VERSION 5.8 ;
BUSBITCHARS "[]" ;
DIVIDERCHAR "/" ;
UNITS
    DATABASE MICRONS 1000 ;
END UNITS

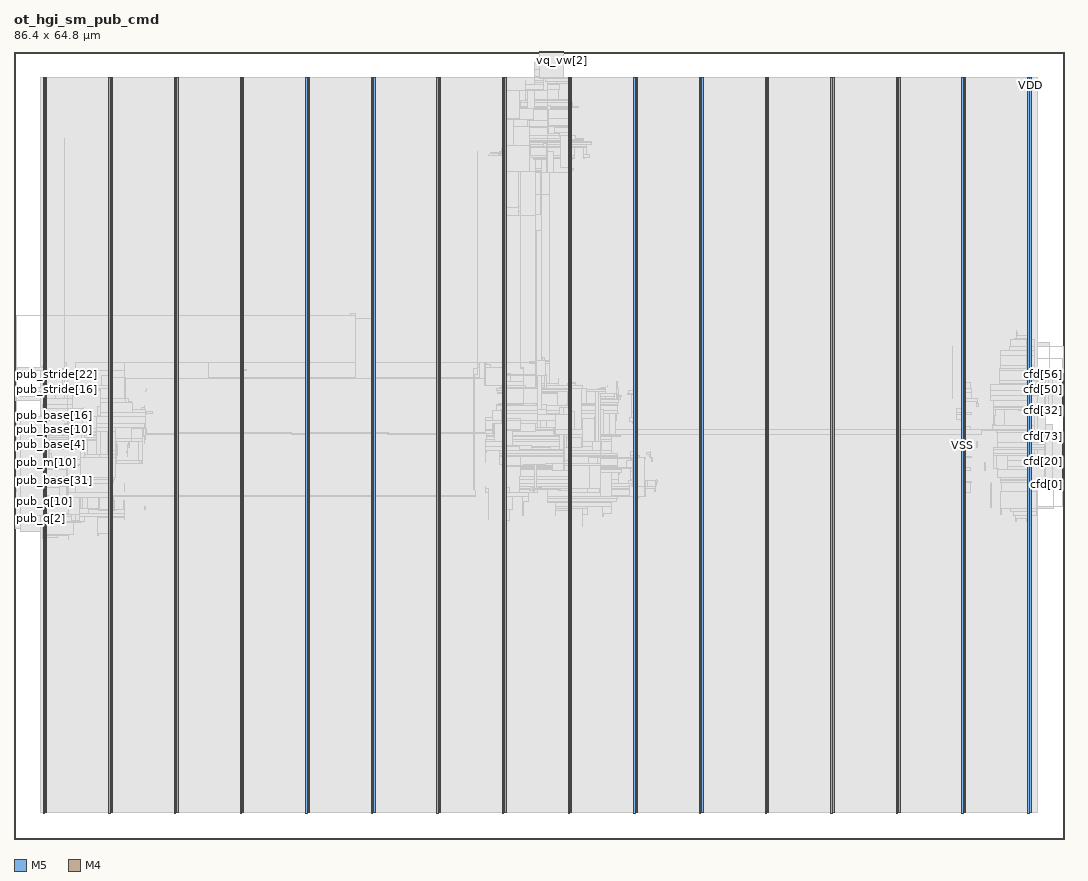
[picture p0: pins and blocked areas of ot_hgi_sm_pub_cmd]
MACRO ot_hgi_sm_pub_cmd
  FOREIGN ot_hgi_sm_pub_cmd 0 0 ;
  CLASS BLOCK ;
  SIZE 86.4 BY 64.8 ;
  PIN agg_r
    DIRECTION INPUT ;
    USE SIGNAL ;
    PORT
      LAYER M5 ;
        RECT  43.248 64.716 43.272 64.8 ;
    END
  END agg_r
  PIN cfd[0]
    DIRECTION OUTPUT ;
    USE SIGNAL ;
    PORT
      LAYER M4 ;
        RECT  86.316 29.136 86.4 29.16 ;
    END
  END cfd[0]
  PIN cfd[10]
    DIRECTION OUTPUT ;
    USE SIGNAL ;
    PORT
      LAYER M4 ;
        RECT  86.316 30.096 86.4 30.12 ;
    END
  END cfd[10]
  PIN cfd[11]
    DIRECTION OUTPUT ;
    USE SIGNAL ;
    PORT
      LAYER M4 ;
        RECT  86.316 30.192 86.4 30.216 ;
    END
  END cfd[11]
  PIN cfd[12]
    DIRECTION OUTPUT ;
    USE SIGNAL ;
    PORT
      LAYER M4 ;
        RECT  86.316 30.288 86.4 30.312 ;
    END
  END cfd[12]
  PIN cfd[13]
    DIRECTION OUTPUT ;
    USE SIGNAL ;
    PORT
      LAYER M4 ;
        RECT  86.316 30.384 86.4 30.408 ;
    END
  END cfd[13]
  PIN cfd[14]
    DIRECTION OUTPUT ;
    USE SIGNAL ;
    PORT
      LAYER M4 ;
        RECT  86.316 30.48 86.4 30.504 ;
    END
  END cfd[14]
  PIN cfd[15]
    DIRECTION OUTPUT ;
    USE SIGNAL ;
    PORT
      LAYER M4 ;
        RECT  86.316 30.576 86.4 30.6 ;
    END
  END cfd[15]
  PIN cfd[16]
    DIRECTION OUTPUT ;
    USE SIGNAL ;
    PORT
      LAYER M4 ;
        RECT  86.316 30.672 86.4 30.696 ;
    END
  END cfd[16]
  PIN cfd[17]
    DIRECTION OUTPUT ;
    USE SIGNAL ;
    PORT
      LAYER M4 ;
        RECT  86.316 30.768 86.4 30.792 ;
    END
  END cfd[17]
  PIN cfd[18]
    DIRECTION OUTPUT ;
    USE SIGNAL ;
    PORT
      LAYER M4 ;
        RECT  86.316 30.864 86.4 30.888 ;
    END
  END cfd[18]
  PIN cfd[19]
    DIRECTION OUTPUT ;
    USE SIGNAL ;
    PORT
      LAYER M4 ;
        RECT  86.316 30.96 86.4 30.984 ;
    END
  END cfd[19]
  PIN cfd[1]
    DIRECTION OUTPUT ;
    USE SIGNAL ;
    PORT
      LAYER M4 ;
        RECT  86.316 29.232 86.4 29.256 ;
    END
  END cfd[1]
  PIN cfd[20]
    DIRECTION OUTPUT ;
    USE SIGNAL ;
    PORT
      LAYER M4 ;
        RECT  86.316 31.056 86.4 31.08 ;
    END
  END cfd[20]
  PIN cfd[21]
    DIRECTION OUTPUT ;
    USE SIGNAL ;
    PORT
      LAYER M4 ;
        RECT  86.316 31.152 86.4 31.176 ;
    END
  END cfd[21]
  PIN cfd[22]
    DIRECTION OUTPUT ;
    USE SIGNAL ;
    PORT
      LAYER M4 ;
        RECT  86.316 31.248 86.4 31.272 ;
    END
  END cfd[22]
  PIN cfd[23]
    DIRECTION OUTPUT ;
    USE SIGNAL ;
    PORT
      LAYER M4 ;
        RECT  86.316 31.344 86.4 31.368 ;
    END
  END cfd[23]
  PIN cfd[24]
    DIRECTION OUTPUT ;
    USE SIGNAL ;
    PORT
      LAYER M4 ;
        RECT  86.316 31.44 86.4 31.464 ;
    END
  END cfd[24]
  PIN cfd[25]
    DIRECTION OUTPUT ;
    USE SIGNAL ;
    PORT
      LAYER M4 ;
        RECT  86.316 31.536 86.4 31.56 ;
    END
  END cfd[25]
  PIN cfd[26]
    DIRECTION OUTPUT ;
    USE SIGNAL ;
    PORT
      LAYER M4 ;
        RECT  86.316 31.632 86.4 31.656 ;
    END
  END cfd[26]
  PIN cfd[27]
    DIRECTION OUTPUT ;
    USE SIGNAL ;
    PORT
      LAYER M4 ;
        RECT  86.316 31.728 86.4 31.752 ;
    END
  END cfd[27]
  PIN cfd[28]
    DIRECTION OUTPUT ;
    USE SIGNAL ;
    PORT
      LAYER M4 ;
        RECT  86.316 31.824 86.4 31.848 ;
    END
  END cfd[28]
  PIN cfd[29]
    DIRECTION OUTPUT ;
    USE SIGNAL ;
    PORT
      LAYER M4 ;
        RECT  86.316 31.92 86.4 31.944 ;
    END
  END cfd[29]
  PIN cfd[2]
    DIRECTION OUTPUT ;
    USE SIGNAL ;
    PORT
      LAYER M4 ;
        RECT  86.316 29.328 86.4 29.352 ;
    END
  END cfd[2]
  PIN cfd[30]
    DIRECTION OUTPUT ;
    USE SIGNAL ;
    PORT
      LAYER M4 ;
        RECT  86.316 32.016 86.4 32.04 ;
    END
  END cfd[30]
  PIN cfd[31]
    DIRECTION OUTPUT ;
    USE SIGNAL ;
    PORT
      LAYER M4 ;
        RECT  86.316 32.112 86.4 32.136 ;
    END
  END cfd[31]
  PIN cfd[32]
    DIRECTION OUTPUT ;
    USE SIGNAL ;
    PORT
      LAYER M4 ;
        RECT  86.316 35.28 86.4 35.304 ;
    END
  END cfd[32]
  PIN cfd[33]
    DIRECTION OUTPUT ;
    USE SIGNAL ;
    PORT
      LAYER M4 ;
        RECT  86.316 35.376 86.4 35.4 ;
    END
  END cfd[33]
  PIN cfd[34]
    DIRECTION OUTPUT ;
    USE SIGNAL ;
    PORT
      LAYER M4 ;
        RECT  86.316 35.472 86.4 35.496 ;
    END
  END cfd[34]
  PIN cfd[35]
    DIRECTION OUTPUT ;
    USE SIGNAL ;
    PORT
      LAYER M4 ;
        RECT  86.316 35.568 86.4 35.592 ;
    END
  END cfd[35]
  PIN cfd[36]
    DIRECTION OUTPUT ;
    USE SIGNAL ;
    PORT
      LAYER M4 ;
        RECT  86.316 35.664 86.4 35.688 ;
    END
  END cfd[36]
  PIN cfd[37]
    DIRECTION OUTPUT ;
    USE SIGNAL ;
    PORT
      LAYER M4 ;
        RECT  86.316 35.76 86.4 35.784 ;
    END
  END cfd[37]
  PIN cfd[38]
    DIRECTION OUTPUT ;
    USE SIGNAL ;
    PORT
      LAYER M4 ;
        RECT  86.316 35.856 86.4 35.88 ;
    END
  END cfd[38]
  PIN cfd[39]
    DIRECTION OUTPUT ;
    USE SIGNAL ;
    PORT
      LAYER M4 ;
        RECT  86.316 35.952 86.4 35.976 ;
    END
  END cfd[39]
  PIN cfd[3]
    DIRECTION OUTPUT ;
    USE SIGNAL ;
    PORT
      LAYER M4 ;
        RECT  86.316 29.424 86.4 29.448 ;
    END
  END cfd[3]
  PIN cfd[40]
    DIRECTION OUTPUT ;
    USE SIGNAL ;
    PORT
      LAYER M4 ;
        RECT  86.316 36.048 86.4 36.072 ;
    END
  END cfd[40]
  PIN cfd[41]
    DIRECTION OUTPUT ;
    USE SIGNAL ;
    PORT
      LAYER M4 ;
        RECT  86.316 36.144 86.4 36.168 ;
    END
  END cfd[41]
  PIN cfd[42]
    DIRECTION OUTPUT ;
    USE SIGNAL ;
    PORT
      LAYER M4 ;
        RECT  86.316 36.24 86.4 36.264 ;
    END
  END cfd[42]
  PIN cfd[43]
    DIRECTION OUTPUT ;
    USE SIGNAL ;
    PORT
      LAYER M4 ;
        RECT  86.316 36.336 86.4 36.36 ;
    END
  END cfd[43]
  PIN cfd[44]
    DIRECTION OUTPUT ;
    USE SIGNAL ;
    PORT
      LAYER M4 ;
        RECT  86.316 36.432 86.4 36.456 ;
    END
  END cfd[44]
  PIN cfd[45]
    DIRECTION OUTPUT ;
    USE SIGNAL ;
    PORT
      LAYER M4 ;
        RECT  86.316 36.528 86.4 36.552 ;
    END
  END cfd[45]
  PIN cfd[46]
    DIRECTION OUTPUT ;
    USE SIGNAL ;
    PORT
      LAYER M4 ;
        RECT  86.316 36.624 86.4 36.648 ;
    END
  END cfd[46]
  PIN cfd[47]
    DIRECTION OUTPUT ;
    USE SIGNAL ;
    PORT
      LAYER M4 ;
        RECT  86.316 36.72 86.4 36.744 ;
    END
  END cfd[47]
  PIN cfd[48]
    DIRECTION OUTPUT ;
    USE SIGNAL ;
    PORT
      LAYER M4 ;
        RECT  86.316 36.816 86.4 36.84 ;
    END
  END cfd[48]
  PIN cfd[49]
    DIRECTION OUTPUT ;
    USE SIGNAL ;
    PORT
      LAYER M4 ;
        RECT  86.316 36.912 86.4 36.936 ;
    END
  END cfd[49]
  PIN cfd[4]
    DIRECTION OUTPUT ;
    USE SIGNAL ;
    PORT
      LAYER M4 ;
        RECT  86.316 29.52 86.4 29.544 ;
    END
  END cfd[4]
  PIN cfd[50]
    DIRECTION OUTPUT ;
    USE SIGNAL ;
    PORT
      LAYER M4 ;
        RECT  86.316 37.008 86.4 37.032 ;
    END
  END cfd[50]
  PIN cfd[51]
    DIRECTION OUTPUT ;
    USE SIGNAL ;
    PORT
      LAYER M4 ;
        RECT  86.316 37.104 86.4 37.128 ;
    END
  END cfd[51]
  PIN cfd[52]
    DIRECTION OUTPUT ;
    USE SIGNAL ;
    PORT
      LAYER M4 ;
        RECT  86.316 37.2 86.4 37.224 ;
    END
  END cfd[52]
  PIN cfd[53]
    DIRECTION OUTPUT ;
    USE SIGNAL ;
    PORT
      LAYER M4 ;
        RECT  86.316 37.296 86.4 37.32 ;
    END
  END cfd[53]
  PIN cfd[54]
    DIRECTION OUTPUT ;
    USE SIGNAL ;
    PORT
      LAYER M4 ;
        RECT  86.316 37.392 86.4 37.416 ;
    END
  END cfd[54]
  PIN cfd[55]
    DIRECTION OUTPUT ;
    USE SIGNAL ;
    PORT
      LAYER M4 ;
        RECT  86.316 37.488 86.4 37.512 ;
    END
  END cfd[55]
  PIN cfd[56]
    DIRECTION OUTPUT ;
    USE SIGNAL ;
    PORT
      LAYER M4 ;
        RECT  86.316 37.584 86.4 37.608 ;
    END
  END cfd[56]
  PIN cfd[57]
    DIRECTION OUTPUT ;
    USE SIGNAL ;
    PORT
      LAYER M4 ;
        RECT  86.316 37.68 86.4 37.704 ;
    END
  END cfd[57]
  PIN cfd[58]
    DIRECTION OUTPUT ;
    USE SIGNAL ;
    PORT
      LAYER M4 ;
        RECT  86.316 37.776 86.4 37.8 ;
    END
  END cfd[58]
  PIN cfd[59]
    DIRECTION OUTPUT ;
    USE SIGNAL ;
    PORT
      LAYER M4 ;
        RECT  86.316 37.872 86.4 37.896 ;
    END
  END cfd[59]
  PIN cfd[5]
    DIRECTION OUTPUT ;
    USE SIGNAL ;
    PORT
      LAYER M4 ;
        RECT  86.316 29.616 86.4 29.64 ;
    END
  END cfd[5]
  PIN cfd[60]
    DIRECTION OUTPUT ;
    USE SIGNAL ;
    PORT
      LAYER M4 ;
        RECT  86.316 37.968 86.4 37.992 ;
    END
  END cfd[60]
  PIN cfd[61]
    DIRECTION OUTPUT ;
    USE SIGNAL ;
    PORT
      LAYER M4 ;
        RECT  86.316 38.064 86.4 38.088 ;
    END
  END cfd[61]
  PIN cfd[62]
    DIRECTION OUTPUT ;
    USE SIGNAL ;
    PORT
      LAYER M4 ;
        RECT  86.316 38.16 86.4 38.184 ;
    END
  END cfd[62]
  PIN cfd[63]
    DIRECTION OUTPUT ;
    USE SIGNAL ;
    PORT
      LAYER M4 ;
        RECT  86.316 38.256 86.4 38.28 ;
    END
  END cfd[63]
  PIN cfd[64]
    DIRECTION OUTPUT ;
    USE SIGNAL ;
    PORT
      LAYER M4 ;
        RECT  86.316 32.208 86.4 32.232 ;
    END
  END cfd[64]
  PIN cfd[65]
    DIRECTION OUTPUT ;
    USE SIGNAL ;
    PORT
      LAYER M4 ;
        RECT  86.316 32.304 86.4 32.328 ;
    END
  END cfd[65]
  PIN cfd[66]
    DIRECTION OUTPUT ;
    USE SIGNAL ;
    PORT
      LAYER M4 ;
        RECT  86.316 32.4 86.4 32.424 ;
    END
  END cfd[66]
  PIN cfd[67]
    DIRECTION OUTPUT ;
    USE SIGNAL ;
    PORT
      LAYER M4 ;
        RECT  86.316 32.496 86.4 32.52 ;
    END
  END cfd[67]
  PIN cfd[68]
    DIRECTION OUTPUT ;
    USE SIGNAL ;
    PORT
      LAYER M4 ;
        RECT  86.316 32.592 86.4 32.616 ;
    END
  END cfd[68]
  PIN cfd[69]
    DIRECTION OUTPUT ;
    USE SIGNAL ;
    PORT
      LAYER M4 ;
        RECT  86.316 32.688 86.4 32.712 ;
    END
  END cfd[69]
  PIN cfd[6]
    DIRECTION OUTPUT ;
    USE SIGNAL ;
    PORT
      LAYER M4 ;
        RECT  86.316 29.712 86.4 29.736 ;
    END
  END cfd[6]
  PIN cfd[70]
    DIRECTION OUTPUT ;
    USE SIGNAL ;
    PORT
      LAYER M4 ;
        RECT  86.316 32.784 86.4 32.808 ;
    END
  END cfd[70]
  PIN cfd[71]
    DIRECTION OUTPUT ;
    USE SIGNAL ;
    PORT
      LAYER M4 ;
        RECT  86.316 32.88 86.4 32.904 ;
    END
  END cfd[71]
  PIN cfd[72]
    DIRECTION OUTPUT ;
    USE SIGNAL ;
    PORT
      LAYER M4 ;
        RECT  86.316 32.976 86.4 33 ;
    END
  END cfd[72]
  PIN cfd[73]
    DIRECTION OUTPUT ;
    USE SIGNAL ;
    PORT
      LAYER M4 ;
        RECT  86.316 33.072 86.4 33.096 ;
    END
  END cfd[73]
  PIN cfd[74]
    DIRECTION OUTPUT ;
    USE SIGNAL ;
    PORT
      LAYER M4 ;
        RECT  86.316 33.168 86.4 33.192 ;
    END
  END cfd[74]
  PIN cfd[7]
    DIRECTION OUTPUT ;
    USE SIGNAL ;
    PORT
      LAYER M4 ;
        RECT  86.316 29.808 86.4 29.832 ;
    END
  END cfd[7]
  PIN cfd[8]
    DIRECTION OUTPUT ;
    USE SIGNAL ;
    PORT
      LAYER M4 ;
        RECT  86.316 29.904 86.4 29.928 ;
    END
  END cfd[8]
  PIN cfd[9]
    DIRECTION OUTPUT ;
    USE SIGNAL ;
    PORT
      LAYER M4 ;
        RECT  86.316 30 86.4 30.024 ;
    END
  END cfd[9]
  PIN cgo
    DIRECTION OUTPUT ;
    USE SIGNAL ;
    PORT
      LAYER M4 ;
        RECT  86.316 33.264 86.4 33.288 ;
    END
  END cgo
  PIN clk
    DIRECTION INPUT ;
    USE SIGNAL ;
    PORT
      LAYER M4 ;
        RECT  0 32.592 0.084 32.616 ;
    END
  END clk
  PIN dn_l[0]
    DIRECTION INPUT ;
    USE SIGNAL ;
    PORT
      LAYER M5 ;
        RECT  43.344 64.716 43.368 64.8 ;
    END
  END dn_l[0]
  PIN dn_l[1]
    DIRECTION INPUT ;
    USE SIGNAL ;
    PORT
      LAYER M5 ;
        RECT  43.44 64.716 43.464 64.8 ;
    END
  END dn_l[1]
  PIN dn_l[2]
    DIRECTION INPUT ;
    USE SIGNAL ;
    PORT
      LAYER M5 ;
        RECT  43.536 64.716 43.56 64.8 ;
    END
  END dn_l[2]
  PIN dn_l[3]
    DIRECTION INPUT ;
    USE SIGNAL ;
    PORT
      LAYER M5 ;
        RECT  43.632 64.716 43.656 64.8 ;
    END
  END dn_l[3]
  PIN dn_l[4]
    DIRECTION INPUT ;
    USE SIGNAL ;
    PORT
      LAYER M5 ;
        RECT  43.728 64.716 43.752 64.8 ;
    END
  END dn_l[4]
  PIN dn_l[5]
    DIRECTION INPUT ;
    USE SIGNAL ;
    PORT
      LAYER M5 ;
        RECT  43.824 64.716 43.848 64.8 ;
    END
  END dn_l[5]
  PIN dn_l[6]
    DIRECTION INPUT ;
    USE SIGNAL ;
    PORT
      LAYER M5 ;
        RECT  43.92 64.716 43.944 64.8 ;
    END
  END dn_l[6]
  PIN dn_l[7]
    DIRECTION INPUT ;
    USE SIGNAL ;
    PORT
      LAYER M5 ;
        RECT  44.016 64.716 44.04 64.8 ;
    END
  END dn_l[7]
  PIN ft_l[0]
    DIRECTION INPUT ;
    USE SIGNAL ;
    PORT
      LAYER M5 ;
        RECT  44.112 64.716 44.136 64.8 ;
    END
  END ft_l[0]
  PIN ft_l[1]
    DIRECTION INPUT ;
    USE SIGNAL ;
    PORT
      LAYER M5 ;
        RECT  44.208 64.716 44.232 64.8 ;
    END
  END ft_l[1]
  PIN ft_l[2]
    DIRECTION INPUT ;
    USE SIGNAL ;
    PORT
      LAYER M5 ;
        RECT  44.304 64.716 44.328 64.8 ;
    END
  END ft_l[2]
  PIN ft_l[3]
    DIRECTION INPUT ;
    USE SIGNAL ;
    PORT
      LAYER M5 ;
        RECT  44.4 64.716 44.424 64.8 ;
    END
  END ft_l[3]
  PIN ft_l[4]
    DIRECTION INPUT ;
    USE SIGNAL ;
    PORT
      LAYER M5 ;
        RECT  44.496 64.716 44.52 64.8 ;
    END
  END ft_l[4]
  PIN ft_l[5]
    DIRECTION INPUT ;
    USE SIGNAL ;
    PORT
      LAYER M5 ;
        RECT  44.592 64.716 44.616 64.8 ;
    END
  END ft_l[5]
  PIN ft_l[6]
    DIRECTION INPUT ;
    USE SIGNAL ;
    PORT
      LAYER M5 ;
        RECT  44.688 64.716 44.712 64.8 ;
    END
  END ft_l[6]
  PIN ft_l[7]
    DIRECTION INPUT ;
    USE SIGNAL ;
    PORT
      LAYER M5 ;
        RECT  44.784 64.716 44.808 64.8 ;
    END
  END ft_l[7]
  PIN pub_base[0]
    DIRECTION INPUT ;
    USE SIGNAL ;
    PORT
      LAYER M4 ;
        RECT  0 32.688 0.084 32.712 ;
    END
  END pub_base[0]
  PIN pub_base[10]
    DIRECTION INPUT ;
    USE SIGNAL ;
    PORT
      LAYER M4 ;
        RECT  0 33.648 0.084 33.672 ;
    END
  END pub_base[10]
  PIN pub_base[11]
    DIRECTION INPUT ;
    USE SIGNAL ;
    PORT
      LAYER M4 ;
        RECT  0 33.744 0.084 33.768 ;
    END
  END pub_base[11]
  PIN pub_base[12]
    DIRECTION INPUT ;
    USE SIGNAL ;
    PORT
      LAYER M4 ;
        RECT  0 33.84 0.084 33.864 ;
    END
  END pub_base[12]
  PIN pub_base[13]
    DIRECTION INPUT ;
    USE SIGNAL ;
    PORT
      LAYER M4 ;
        RECT  0 33.936 0.084 33.96 ;
    END
  END pub_base[13]
  PIN pub_base[14]
    DIRECTION INPUT ;
    USE SIGNAL ;
    PORT
      LAYER M4 ;
        RECT  0 34.032 0.084 34.056 ;
    END
  END pub_base[14]
  PIN pub_base[15]
    DIRECTION INPUT ;
    USE SIGNAL ;
    PORT
      LAYER M4 ;
        RECT  0 34.128 0.084 34.152 ;
    END
  END pub_base[15]
  PIN pub_base[16]
    DIRECTION INPUT ;
    USE SIGNAL ;
    PORT
      LAYER M4 ;
        RECT  0 34.224 0.084 34.248 ;
    END
  END pub_base[16]
  PIN pub_base[17]
    DIRECTION INPUT ;
    USE SIGNAL ;
    PORT
      LAYER M4 ;
        RECT  0 34.32 0.084 34.344 ;
    END
  END pub_base[17]
  PIN pub_base[18]
    DIRECTION INPUT ;
    USE SIGNAL ;
    PORT
      LAYER M4 ;
        RECT  0 34.416 0.084 34.44 ;
    END
  END pub_base[18]
  PIN pub_base[19]
    DIRECTION INPUT ;
    USE SIGNAL ;
    PORT
      LAYER M4 ;
        RECT  0 34.512 0.084 34.536 ;
    END
  END pub_base[19]
  PIN pub_base[1]
    DIRECTION INPUT ;
    USE SIGNAL ;
    PORT
      LAYER M4 ;
        RECT  0 32.784 0.084 32.808 ;
    END
  END pub_base[1]
  PIN pub_base[20]
    DIRECTION INPUT ;
    USE SIGNAL ;
    PORT
      LAYER M4 ;
        RECT  0 34.608 0.084 34.632 ;
    END
  END pub_base[20]
  PIN pub_base[21]
    DIRECTION INPUT ;
    USE SIGNAL ;
    PORT
      LAYER M4 ;
        RECT  0 34.704 0.084 34.728 ;
    END
  END pub_base[21]
  PIN pub_base[22]
    DIRECTION INPUT ;
    USE SIGNAL ;
    PORT
      LAYER M4 ;
        RECT  0 34.8 0.084 34.824 ;
    END
  END pub_base[22]
  PIN pub_base[23]
    DIRECTION INPUT ;
    USE SIGNAL ;
    PORT
      LAYER M4 ;
        RECT  0 34.896 0.084 34.92 ;
    END
  END pub_base[23]
  PIN pub_base[24]
    DIRECTION INPUT ;
    USE SIGNAL ;
    PORT
      LAYER M4 ;
        RECT  0 34.992 0.084 35.016 ;
    END
  END pub_base[24]
  PIN pub_base[25]
    DIRECTION INPUT ;
    USE SIGNAL ;
    PORT
      LAYER M4 ;
        RECT  0 35.088 0.084 35.112 ;
    END
  END pub_base[25]
  PIN pub_base[26]
    DIRECTION INPUT ;
    USE SIGNAL ;
    PORT
      LAYER M4 ;
        RECT  0 35.184 0.084 35.208 ;
    END
  END pub_base[26]
  PIN pub_base[27]
    DIRECTION INPUT ;
    USE SIGNAL ;
    PORT
      LAYER M4 ;
        RECT  0 35.28 0.084 35.304 ;
    END
  END pub_base[27]
  PIN pub_base[28]
    DIRECTION INPUT ;
    USE SIGNAL ;
    PORT
      LAYER M4 ;
        RECT  0 35.376 0.084 35.4 ;
    END
  END pub_base[28]
  PIN pub_base[29]
    DIRECTION INPUT ;
    USE SIGNAL ;
    PORT
      LAYER M4 ;
        RECT  0 35.472 0.084 35.496 ;
    END
  END pub_base[29]
  PIN pub_base[2]
    DIRECTION INPUT ;
    USE SIGNAL ;
    PORT
      LAYER M4 ;
        RECT  0 32.88 0.084 32.904 ;
    END
  END pub_base[2]
  PIN pub_base[30]
    DIRECTION INPUT ;
    USE SIGNAL ;
    PORT
      LAYER M4 ;
        RECT  0 35.568 0.084 35.592 ;
    END
  END pub_base[30]
  PIN pub_base[31]
    DIRECTION INPUT ;
    USE SIGNAL ;
    PORT
      LAYER M4 ;
        RECT  0 29.52 0.084 29.544 ;
    END
  END pub_base[31]
  PIN pub_base[32]
    DIRECTION INPUT ;
    USE SIGNAL ;
    PORT
      LAYER M4 ;
        RECT  0 29.616 0.084 29.64 ;
    END
  END pub_base[32]
  PIN pub_base[33]
    DIRECTION INPUT ;
    USE SIGNAL ;
    PORT
      LAYER M4 ;
        RECT  0 29.712 0.084 29.736 ;
    END
  END pub_base[33]
  PIN pub_base[34]
    DIRECTION INPUT ;
    USE SIGNAL ;
    PORT
      LAYER M4 ;
        RECT  0 29.808 0.084 29.832 ;
    END
  END pub_base[34]
  PIN pub_base[35]
    DIRECTION INPUT ;
    USE SIGNAL ;
    PORT
      LAYER M4 ;
        RECT  0 29.904 0.084 29.928 ;
    END
  END pub_base[35]
  PIN pub_base[36]
    DIRECTION INPUT ;
    USE SIGNAL ;
    PORT
      LAYER M4 ;
        RECT  0 30 0.084 30.024 ;
    END
  END pub_base[36]
  PIN pub_base[37]
    DIRECTION INPUT ;
    USE SIGNAL ;
    PORT
      LAYER M4 ;
        RECT  0 30.096 0.084 30.12 ;
    END
  END pub_base[37]
  PIN pub_base[38]
    DIRECTION INPUT ;
    USE SIGNAL ;
    PORT
      LAYER M4 ;
        RECT  0 30.192 0.084 30.216 ;
    END
  END pub_base[38]
  PIN pub_base[39]
    DIRECTION INPUT ;
    USE SIGNAL ;
    PORT
      LAYER M4 ;
        RECT  0 30.288 0.084 30.312 ;
    END
  END pub_base[39]
  PIN pub_base[3]
    DIRECTION INPUT ;
    USE SIGNAL ;
    PORT
      LAYER M4 ;
        RECT  0 32.976 0.084 33 ;
    END
  END pub_base[3]
  PIN pub_base[4]
    DIRECTION INPUT ;
    USE SIGNAL ;
    PORT
      LAYER M4 ;
        RECT  0 33.072 0.084 33.096 ;
    END
  END pub_base[4]
  PIN pub_base[5]
    DIRECTION INPUT ;
    USE SIGNAL ;
    PORT
      LAYER M4 ;
        RECT  0 33.168 0.084 33.192 ;
    END
  END pub_base[5]
  PIN pub_base[6]
    DIRECTION INPUT ;
    USE SIGNAL ;
    PORT
      LAYER M4 ;
        RECT  0 33.264 0.084 33.288 ;
    END
  END pub_base[6]
  PIN pub_base[7]
    DIRECTION INPUT ;
    USE SIGNAL ;
    PORT
      LAYER M4 ;
        RECT  0 33.36 0.084 33.384 ;
    END
  END pub_base[7]
  PIN pub_base[8]
    DIRECTION INPUT ;
    USE SIGNAL ;
    PORT
      LAYER M4 ;
        RECT  0 33.456 0.084 33.48 ;
    END
  END pub_base[8]
  PIN pub_base[9]
    DIRECTION INPUT ;
    USE SIGNAL ;
    PORT
      LAYER M4 ;
        RECT  0 33.552 0.084 33.576 ;
    END
  END pub_base[9]
  PIN pub_bf16
    DIRECTION INPUT ;
    USE SIGNAL ;
    PORT
      LAYER M4 ;
        RECT  0 30.384 0.084 30.408 ;
    END
  END pub_bf16
  PIN pub_done
    DIRECTION OUTPUT ;
    USE SIGNAL ;
    PORT
      LAYER M4 ;
        RECT  0 30.48 0.084 30.504 ;
    END
  END pub_done
  PIN pub_fault
    DIRECTION OUTPUT ;
    USE SIGNAL ;
    PORT
      LAYER M4 ;
        RECT  0 30.576 0.084 30.6 ;
    END
  END pub_fault
  PIN pub_m[0]
    DIRECTION INPUT ;
    USE SIGNAL ;
    PORT
      LAYER M4 ;
        RECT  0 30.672 0.084 30.696 ;
    END
  END pub_m[0]
  PIN pub_m[10]
    DIRECTION INPUT ;
    USE SIGNAL ;
    PORT
      LAYER M4 ;
        RECT  0 31.632 0.084 31.656 ;
    END
  END pub_m[10]
  PIN pub_m[11]
    DIRECTION INPUT ;
    USE SIGNAL ;
    PORT
      LAYER M4 ;
        RECT  0 31.728 0.084 31.752 ;
    END
  END pub_m[11]
  PIN pub_m[12]
    DIRECTION INPUT ;
    USE SIGNAL ;
    PORT
      LAYER M4 ;
        RECT  0 31.824 0.084 31.848 ;
    END
  END pub_m[12]
  PIN pub_m[13]
    DIRECTION INPUT ;
    USE SIGNAL ;
    PORT
      LAYER M4 ;
        RECT  0 31.92 0.084 31.944 ;
    END
  END pub_m[13]
  PIN pub_m[14]
    DIRECTION INPUT ;
    USE SIGNAL ;
    PORT
      LAYER M4 ;
        RECT  0 32.016 0.084 32.04 ;
    END
  END pub_m[14]
  PIN pub_m[15]
    DIRECTION INPUT ;
    USE SIGNAL ;
    PORT
      LAYER M4 ;
        RECT  0 32.112 0.084 32.136 ;
    END
  END pub_m[15]
  PIN pub_m[16]
    DIRECTION INPUT ;
    USE SIGNAL ;
    PORT
      LAYER M4 ;
        RECT  0 32.208 0.084 32.232 ;
    END
  END pub_m[16]
  PIN pub_m[17]
    DIRECTION INPUT ;
    USE SIGNAL ;
    PORT
      LAYER M4 ;
        RECT  0 32.304 0.084 32.328 ;
    END
  END pub_m[17]
  PIN pub_m[18]
    DIRECTION INPUT ;
    USE SIGNAL ;
    PORT
      LAYER M4 ;
        RECT  0 32.4 0.084 32.424 ;
    END
  END pub_m[18]
  PIN pub_m[19]
    DIRECTION INPUT ;
    USE SIGNAL ;
    PORT
      LAYER M4 ;
        RECT  0 32.496 0.084 32.52 ;
    END
  END pub_m[19]
  PIN pub_m[1]
    DIRECTION INPUT ;
    USE SIGNAL ;
    PORT
      LAYER M4 ;
        RECT  0 30.768 0.084 30.792 ;
    END
  END pub_m[1]
  PIN pub_m[2]
    DIRECTION INPUT ;
    USE SIGNAL ;
    PORT
      LAYER M4 ;
        RECT  0 30.864 0.084 30.888 ;
    END
  END pub_m[2]
  PIN pub_m[3]
    DIRECTION INPUT ;
    USE SIGNAL ;
    PORT
      LAYER M4 ;
        RECT  0 30.96 0.084 30.984 ;
    END
  END pub_m[3]
  PIN pub_m[4]
    DIRECTION INPUT ;
    USE SIGNAL ;
    PORT
      LAYER M4 ;
        RECT  0 31.056 0.084 31.08 ;
    END
  END pub_m[4]
  PIN pub_m[5]
    DIRECTION INPUT ;
    USE SIGNAL ;
    PORT
      LAYER M4 ;
        RECT  0 31.152 0.084 31.176 ;
    END
  END pub_m[5]
  PIN pub_m[6]
    DIRECTION INPUT ;
    USE SIGNAL ;
    PORT
      LAYER M4 ;
        RECT  0 31.248 0.084 31.272 ;
    END
  END pub_m[6]
  PIN pub_m[7]
    DIRECTION INPUT ;
    USE SIGNAL ;
    PORT
      LAYER M4 ;
        RECT  0 31.344 0.084 31.368 ;
    END
  END pub_m[7]
  PIN pub_m[8]
    DIRECTION INPUT ;
    USE SIGNAL ;
    PORT
      LAYER M4 ;
        RECT  0 31.44 0.084 31.464 ;
    END
  END pub_m[8]
  PIN pub_m[9]
    DIRECTION INPUT ;
    USE SIGNAL ;
    PORT
      LAYER M4 ;
        RECT  0 31.536 0.084 31.56 ;
    END
  END pub_m[9]
  PIN pub_p[0]
    DIRECTION INPUT ;
    USE SIGNAL ;
    PORT
      LAYER M4 ;
        RECT  0 26.448 0.084 26.472 ;
    END
  END pub_p[0]
  PIN pub_p[1]
    DIRECTION INPUT ;
    USE SIGNAL ;
    PORT
      LAYER M4 ;
        RECT  0 26.544 0.084 26.568 ;
    END
  END pub_p[1]
  PIN pub_p[2]
    DIRECTION INPUT ;
    USE SIGNAL ;
    PORT
      LAYER M4 ;
        RECT  0 26.64 0.084 26.664 ;
    END
  END pub_p[2]
  PIN pub_p[3]
    DIRECTION INPUT ;
    USE SIGNAL ;
    PORT
      LAYER M4 ;
        RECT  0 26.736 0.084 26.76 ;
    END
  END pub_p[3]
  PIN pub_q[0]
    DIRECTION INPUT ;
    USE SIGNAL ;
    PORT
      LAYER M4 ;
        RECT  0 26.832 0.084 26.856 ;
    END
  END pub_q[0]
  PIN pub_q[10]
    DIRECTION INPUT ;
    USE SIGNAL ;
    PORT
      LAYER M4 ;
        RECT  0 27.792 0.084 27.816 ;
    END
  END pub_q[10]
  PIN pub_q[11]
    DIRECTION INPUT ;
    USE SIGNAL ;
    PORT
      LAYER M4 ;
        RECT  0 27.888 0.084 27.912 ;
    END
  END pub_q[11]
  PIN pub_q[12]
    DIRECTION INPUT ;
    USE SIGNAL ;
    PORT
      LAYER M4 ;
        RECT  0 27.984 0.084 28.008 ;
    END
  END pub_q[12]
  PIN pub_q[1]
    DIRECTION INPUT ;
    USE SIGNAL ;
    PORT
      LAYER M4 ;
        RECT  0 26.928 0.084 26.952 ;
    END
  END pub_q[1]
  PIN pub_q[2]
    DIRECTION INPUT ;
    USE SIGNAL ;
    PORT
      LAYER M4 ;
        RECT  0 27.024 0.084 27.048 ;
    END
  END pub_q[2]
  PIN pub_q[3]
    DIRECTION INPUT ;
    USE SIGNAL ;
    PORT
      LAYER M4 ;
        RECT  0 27.12 0.084 27.144 ;
    END
  END pub_q[3]
  PIN pub_q[4]
    DIRECTION INPUT ;
    USE SIGNAL ;
    PORT
      LAYER M4 ;
        RECT  0 27.216 0.084 27.24 ;
    END
  END pub_q[4]
  PIN pub_q[5]
    DIRECTION INPUT ;
    USE SIGNAL ;
    PORT
      LAYER M4 ;
        RECT  0 27.312 0.084 27.336 ;
    END
  END pub_q[5]
  PIN pub_q[6]
    DIRECTION INPUT ;
    USE SIGNAL ;
    PORT
      LAYER M4 ;
        RECT  0 27.408 0.084 27.432 ;
    END
  END pub_q[6]
  PIN pub_q[7]
    DIRECTION INPUT ;
    USE SIGNAL ;
    PORT
      LAYER M4 ;
        RECT  0 27.504 0.084 27.528 ;
    END
  END pub_q[7]
  PIN pub_q[8]
    DIRECTION INPUT ;
    USE SIGNAL ;
    PORT
      LAYER M4 ;
        RECT  0 27.6 0.084 27.624 ;
    END
  END pub_q[8]
  PIN pub_q[9]
    DIRECTION INPUT ;
    USE SIGNAL ;
    PORT
      LAYER M4 ;
        RECT  0 27.696 0.084 27.72 ;
    END
  END pub_q[9]
  PIN pub_rdy
    DIRECTION OUTPUT ;
    USE SIGNAL ;
    PORT
      LAYER M4 ;
        RECT  0 28.08 0.084 28.104 ;
    END
  END pub_rdy
  PIN pub_space[0]
    DIRECTION INPUT ;
    USE SIGNAL ;
    PORT
      LAYER M4 ;
        RECT  0 28.176 0.084 28.2 ;
    END
  END pub_space[0]
  PIN pub_space[1]
    DIRECTION INPUT ;
    USE SIGNAL ;
    PORT
      LAYER M4 ;
        RECT  0 28.272 0.084 28.296 ;
    END
  END pub_space[1]
  PIN pub_stride[0]
    DIRECTION INPUT ;
    USE SIGNAL ;
    PORT
      LAYER M4 ;
        RECT  0 28.368 0.084 28.392 ;
    END
  END pub_stride[0]
  PIN pub_stride[10]
    DIRECTION INPUT ;
    USE SIGNAL ;
    PORT
      LAYER M4 ;
        RECT  0 29.328 0.084 29.352 ;
    END
  END pub_stride[10]
  PIN pub_stride[11]
    DIRECTION INPUT ;
    USE SIGNAL ;
    PORT
      LAYER M4 ;
        RECT  0 29.424 0.084 29.448 ;
    END
  END pub_stride[11]
  PIN pub_stride[12]
    DIRECTION INPUT ;
    USE SIGNAL ;
    PORT
      LAYER M4 ;
        RECT  0 36.624 0.084 36.648 ;
    END
  END pub_stride[12]
  PIN pub_stride[13]
    DIRECTION INPUT ;
    USE SIGNAL ;
    PORT
      LAYER M4 ;
        RECT  0 36.72 0.084 36.744 ;
    END
  END pub_stride[13]
  PIN pub_stride[14]
    DIRECTION INPUT ;
    USE SIGNAL ;
    PORT
      LAYER M4 ;
        RECT  0 36.816 0.084 36.84 ;
    END
  END pub_stride[14]
  PIN pub_stride[15]
    DIRECTION INPUT ;
    USE SIGNAL ;
    PORT
      LAYER M4 ;
        RECT  0 36.912 0.084 36.936 ;
    END
  END pub_stride[15]
  PIN pub_stride[16]
    DIRECTION INPUT ;
    USE SIGNAL ;
    PORT
      LAYER M4 ;
        RECT  0 37.008 0.084 37.032 ;
    END
  END pub_stride[16]
  PIN pub_stride[17]
    DIRECTION INPUT ;
    USE SIGNAL ;
    PORT
      LAYER M4 ;
        RECT  0 37.104 0.084 37.128 ;
    END
  END pub_stride[17]
  PIN pub_stride[18]
    DIRECTION INPUT ;
    USE SIGNAL ;
    PORT
      LAYER M4 ;
        RECT  0 37.2 0.084 37.224 ;
    END
  END pub_stride[18]
  PIN pub_stride[19]
    DIRECTION INPUT ;
    USE SIGNAL ;
    PORT
      LAYER M4 ;
        RECT  0 37.296 0.084 37.32 ;
    END
  END pub_stride[19]
  PIN pub_stride[1]
    DIRECTION INPUT ;
    USE SIGNAL ;
    PORT
      LAYER M4 ;
        RECT  0 28.464 0.084 28.488 ;
    END
  END pub_stride[1]
  PIN pub_stride[20]
    DIRECTION INPUT ;
    USE SIGNAL ;
    PORT
      LAYER M4 ;
        RECT  0 37.392 0.084 37.416 ;
    END
  END pub_stride[20]
  PIN pub_stride[21]
    DIRECTION INPUT ;
    USE SIGNAL ;
    PORT
      LAYER M4 ;
        RECT  0 37.488 0.084 37.512 ;
    END
  END pub_stride[21]
  PIN pub_stride[22]
    DIRECTION INPUT ;
    USE SIGNAL ;
    PORT
      LAYER M4 ;
        RECT  0 37.584 0.084 37.608 ;
    END
  END pub_stride[22]
  PIN pub_stride[23]
    DIRECTION INPUT ;
    USE SIGNAL ;
    PORT
      LAYER M4 ;
        RECT  0 37.68 0.084 37.704 ;
    END
  END pub_stride[23]
  PIN pub_stride[24]
    DIRECTION INPUT ;
    USE SIGNAL ;
    PORT
      LAYER M4 ;
        RECT  0 37.776 0.084 37.8 ;
    END
  END pub_stride[24]
  PIN pub_stride[25]
    DIRECTION INPUT ;
    USE SIGNAL ;
    PORT
      LAYER M4 ;
        RECT  0 37.872 0.084 37.896 ;
    END
  END pub_stride[25]
  PIN pub_stride[26]
    DIRECTION INPUT ;
    USE SIGNAL ;
    PORT
      LAYER M4 ;
        RECT  0 37.968 0.084 37.992 ;
    END
  END pub_stride[26]
  PIN pub_stride[27]
    DIRECTION INPUT ;
    USE SIGNAL ;
    PORT
      LAYER M4 ;
        RECT  0 38.064 0.084 38.088 ;
    END
  END pub_stride[27]
  PIN pub_stride[28]
    DIRECTION INPUT ;
    USE SIGNAL ;
    PORT
      LAYER M4 ;
        RECT  0 38.16 0.084 38.184 ;
    END
  END pub_stride[28]
  PIN pub_stride[29]
    DIRECTION INPUT ;
    USE SIGNAL ;
    PORT
      LAYER M4 ;
        RECT  0 38.256 0.084 38.28 ;
    END
  END pub_stride[29]
  PIN pub_stride[2]
    DIRECTION INPUT ;
    USE SIGNAL ;
    PORT
      LAYER M4 ;
        RECT  0 28.56 0.084 28.584 ;
    END
  END pub_stride[2]
  PIN pub_stride[30]
    DIRECTION INPUT ;
    USE SIGNAL ;
    PORT
      LAYER M4 ;
        RECT  0 38.352 0.084 38.376 ;
    END
  END pub_stride[30]
  PIN pub_stride[31]
    DIRECTION INPUT ;
    USE SIGNAL ;
    PORT
      LAYER M4 ;
        RECT  0 38.448 0.084 38.472 ;
    END
  END pub_stride[31]
  PIN pub_stride[3]
    DIRECTION INPUT ;
    USE SIGNAL ;
    PORT
      LAYER M4 ;
        RECT  0 28.656 0.084 28.68 ;
    END
  END pub_stride[3]
  PIN pub_stride[4]
    DIRECTION INPUT ;
    USE SIGNAL ;
    PORT
      LAYER M4 ;
        RECT  0 28.752 0.084 28.776 ;
    END
  END pub_stride[4]
  PIN pub_stride[5]
    DIRECTION INPUT ;
    USE SIGNAL ;
    PORT
      LAYER M4 ;
        RECT  0 28.848 0.084 28.872 ;
    END
  END pub_stride[5]
  PIN pub_stride[6]
    DIRECTION INPUT ;
    USE SIGNAL ;
    PORT
      LAYER M4 ;
        RECT  0 28.944 0.084 28.968 ;
    END
  END pub_stride[6]
  PIN pub_stride[7]
    DIRECTION INPUT ;
    USE SIGNAL ;
    PORT
      LAYER M4 ;
        RECT  0 29.04 0.084 29.064 ;
    END
  END pub_stride[7]
  PIN pub_stride[8]
    DIRECTION INPUT ;
    USE SIGNAL ;
    PORT
      LAYER M4 ;
        RECT  0 29.136 0.084 29.16 ;
    END
  END pub_stride[8]
  PIN pub_stride[9]
    DIRECTION INPUT ;
    USE SIGNAL ;
    PORT
      LAYER M4 ;
        RECT  0 29.232 0.084 29.256 ;
    END
  END pub_stride[9]
  PIN pub_v
    DIRECTION INPUT ;
    USE SIGNAL ;
    PORT
      LAYER M4 ;
        RECT  0 38.544 0.084 38.568 ;
    END
  END pub_v
  PIN rn
    DIRECTION INPUT ;
    USE SIGNAL ;
    PORT
      LAYER M4 ;
        RECT  0 38.64 0.084 38.664 ;
    END
  END rn
  PIN vq_vw[0]
    DIRECTION INPUT ;
    USE SIGNAL ;
    PORT
      LAYER M5 ;
        RECT  44.88 64.716 44.904 64.8 ;
    END
  END vq_vw[0]
  PIN vq_vw[1]
    DIRECTION INPUT ;
    USE SIGNAL ;
    PORT
      LAYER M5 ;
        RECT  44.976 64.716 45 64.8 ;
    END
  END vq_vw[1]
  PIN vq_vw[2]
    DIRECTION INPUT ;
    USE SIGNAL ;
    PORT
      LAYER M5 ;
        RECT  45.072 64.716 45.096 64.8 ;
    END
  END vq_vw[2]
  PIN vq_vw[3]
    DIRECTION INPUT ;
    USE SIGNAL ;
    PORT
      LAYER M5 ;
        RECT  45.168 64.716 45.192 64.8 ;
    END
  END vq_vw[3]
  PIN VDD
    DIRECTION INOUT ;
    USE POWER ;
    PORT
      LAYER M5 ;
        RECT  83.592 2.151 83.712 62.649 ;
        RECT  78.192 2.151 78.312 62.649 ;
        RECT  72.792 2.151 72.912 62.649 ;
        RECT  67.392 2.151 67.512 62.649 ;
        RECT  61.992 2.151 62.112 62.649 ;
        RECT  56.592 2.151 56.712 62.649 ;
        RECT  51.192 2.151 51.312 62.649 ;
        RECT  45.792 2.151 45.912 62.649 ;
        RECT  40.392 2.151 40.512 62.649 ;
        RECT  34.992 2.151 35.112 62.649 ;
        RECT  29.592 2.151 29.712 62.649 ;
        RECT  24.192 2.151 24.312 62.649 ;
        RECT  18.792 2.151 18.912 62.649 ;
        RECT  13.392 2.151 13.512 62.649 ;
        RECT  7.992 2.151 8.112 62.649 ;
        RECT  2.592 2.151 2.712 62.649 ;
    END
  END VDD
  PIN VSS
    DIRECTION INOUT ;
    USE GROUND ;
    PORT
      LAYER M5 ;
        RECT  83.4 2.137 83.52 62.663 ;
        RECT  78 2.137 78.12 62.663 ;
        RECT  72.6 2.137 72.72 62.663 ;
        RECT  67.2 2.137 67.32 62.663 ;
        RECT  61.8 2.137 61.92 62.663 ;
        RECT  56.4 2.137 56.52 62.663 ;
        RECT  51 2.137 51.12 62.663 ;
        RECT  45.6 2.137 45.72 62.663 ;
        RECT  40.2 2.137 40.32 62.663 ;
        RECT  34.8 2.137 34.92 62.663 ;
        RECT  29.4 2.137 29.52 62.663 ;
        RECT  24 2.137 24.12 62.663 ;
        RECT  18.6 2.137 18.72 62.663 ;
        RECT  13.2 2.137 13.32 62.663 ;
        RECT  7.8 2.137 7.92 62.663 ;
        RECT  2.4 2.137 2.52 62.663 ;
    END
  END VSS
  # OT_OBS_CLOSED layer=M5 d_um=1.536 added=32
  OBS
    LAYER RVTN ;
     RECT  2.16 2.16 84.24 2.295 ;
     RECT  2.16 2.565 84.24 2.835 ;
     RECT  2.16 3.105 84.24 3.375 ;
     RECT  2.16 3.645 84.24 3.915 ;
     RECT  2.16 4.185 84.24 4.455 ;
     RECT  2.16 4.725 84.24 4.995 ;
     RECT  2.16 5.265 84.24 5.535 ;
     RECT  2.16 5.805 84.24 6.075 ;
     RECT  2.16 6.345 84.24 6.615 ;
     RECT  2.16 6.885 84.24 7.155 ;
     RECT  2.16 7.425 84.24 7.695 ;
     RECT  2.16 7.965 84.24 8.235 ;
     RECT  2.16 8.505 84.24 8.775 ;
     RECT  2.16 9.045 84.24 9.315 ;
     RECT  2.16 9.585 84.24 9.855 ;
     RECT  2.16 10.125 84.24 10.395 ;
     RECT  2.16 10.665 84.24 10.935 ;
     RECT  2.16 11.205 84.24 11.475 ;
     RECT  2.16 11.745 84.24 12.015 ;
     RECT  2.16 12.285 84.24 12.555 ;
     RECT  2.16 12.825 84.24 13.095 ;
     RECT  2.16 13.365 84.24 13.635 ;
     RECT  2.16 13.905 84.24 14.175 ;
     RECT  2.16 14.445 84.24 14.715 ;
     RECT  2.16 14.985 84.24 15.255 ;
     RECT  2.16 15.525 84.24 15.795 ;
     RECT  2.16 16.065 84.24 16.335 ;
     RECT  2.16 16.605 84.24 16.875 ;
     RECT  2.16 17.145 84.24 17.415 ;
     RECT  2.16 17.685 84.24 17.955 ;
     RECT  2.16 18.225 84.24 18.495 ;
     RECT  2.16 18.765 84.24 19.035 ;
     RECT  2.16 19.305 84.24 19.575 ;
     RECT  2.16 19.845 84.24 20.115 ;
     RECT  2.16 20.385 84.24 20.655 ;
     RECT  2.16 20.925 84.24 21.195 ;
     RECT  2.16 21.465 84.24 21.735 ;
     RECT  2.16 22.005 84.24 22.275 ;
     RECT  2.16 22.545 84.24 22.815 ;
     RECT  2.16 23.085 84.24 23.355 ;
     RECT  2.16 23.625 84.24 23.895 ;
     RECT  2.16 24.165 84.24 24.435 ;
     RECT  2.16 24.705 84.24 24.975 ;
     RECT  2.16 25.245 84.24 25.515 ;
     RECT  2.16 25.785 84.24 26.055 ;
     RECT  2.16 26.325 84.24 26.595 ;
     RECT  2.16 26.865 84.24 27.135 ;
     RECT  2.16 27.405 84.24 27.675 ;
     RECT  2.16 27.945 84.24 28.215 ;
     RECT  2.16 28.485 84.24 28.755 ;
     RECT  2.16 29.025 84.24 29.295 ;
     RECT  2.16 29.565 84.24 29.835 ;
     RECT  2.16 30.105 84.24 30.375 ;
     RECT  2.16 30.645 84.24 30.915 ;
     RECT  2.16 31.185 84.24 31.455 ;
     RECT  2.16 31.725 84.24 31.995 ;
     RECT  2.16 32.265 84.24 32.535 ;
     RECT  2.16 32.805 84.24 33.075 ;
     RECT  2.16 33.345 84.24 33.615 ;
     RECT  2.16 33.885 84.24 34.155 ;
     RECT  2.16 34.425 84.24 34.695 ;
     RECT  2.16 34.965 84.24 35.235 ;
     RECT  2.16 35.505 84.24 35.775 ;
     RECT  2.16 36.045 84.24 36.315 ;
     RECT  2.16 36.585 84.24 36.855 ;
     RECT  2.16 37.125 84.24 37.395 ;
     RECT  2.16 37.665 84.24 37.935 ;
     RECT  2.16 38.205 84.24 38.475 ;
     RECT  2.16 38.745 84.24 39.015 ;
     RECT  2.16 39.285 84.24 39.555 ;
     RECT  2.16 39.825 84.24 40.095 ;
     RECT  2.16 40.365 84.24 40.635 ;
     RECT  2.16 40.905 84.24 41.175 ;
     RECT  2.16 41.445 84.24 41.715 ;
     RECT  2.16 41.985 84.24 42.255 ;
     RECT  2.16 42.525 84.24 42.795 ;
     RECT  2.16 43.065 84.24 43.335 ;
     RECT  2.16 43.605 84.24 43.875 ;
     RECT  2.16 44.145 84.24 44.415 ;
     RECT  2.16 44.685 84.24 44.955 ;
     RECT  2.16 45.225 84.24 45.495 ;
     RECT  2.16 45.765 84.24 46.035 ;
     RECT  2.16 46.305 84.24 46.575 ;
     RECT  2.16 46.845 84.24 47.115 ;
     RECT  2.16 47.385 84.24 47.655 ;
     RECT  2.16 47.925 84.24 48.195 ;
     RECT  2.16 48.465 84.24 48.735 ;
     RECT  2.16 49.005 84.24 49.275 ;
     RECT  2.16 49.545 84.24 49.815 ;
     RECT  2.16 50.085 84.24 50.355 ;
     RECT  2.16 50.625 84.24 50.895 ;
     RECT  2.16 51.165 84.24 51.435 ;
     RECT  2.16 51.705 84.24 51.975 ;
     RECT  2.16 52.245 84.24 52.515 ;
     RECT  2.16 52.785 84.24 53.055 ;
     RECT  2.16 53.325 84.24 53.595 ;
     RECT  2.16 53.865 84.24 54.135 ;
     RECT  2.16 54.405 84.24 54.675 ;
     RECT  2.16 54.945 84.24 55.215 ;
     RECT  2.16 55.485 84.24 55.755 ;
     RECT  2.16 56.025 84.24 56.295 ;
     RECT  2.16 56.565 84.24 56.835 ;
     RECT  2.16 57.105 84.24 57.375 ;
     RECT  2.16 57.645 84.24 57.915 ;
     RECT  2.16 58.185 84.24 58.455 ;
     RECT  2.16 58.725 84.24 58.995 ;
     RECT  2.16 59.265 84.24 59.535 ;
     RECT  2.16 59.805 84.24 60.075 ;
     RECT  2.16 60.345 84.24 60.615 ;
     RECT  2.16 60.885 84.24 61.155 ;
     RECT  2.16 61.425 84.24 61.695 ;
     RECT  2.16 61.965 84.24 62.235 ;
     RECT  2.16 62.505 84.24 62.64 ;
    LAYER RVTP ;
     RECT  2.16 2.295 84.24 2.565 ;
     RECT  2.16 2.835 84.24 3.105 ;
     RECT  2.16 3.375 84.24 3.645 ;
     RECT  2.16 3.915 84.24 4.185 ;
     RECT  2.16 4.455 84.24 4.725 ;
     RECT  2.16 4.995 84.24 5.265 ;
     RECT  2.16 5.535 84.24 5.805 ;
     RECT  2.16 6.075 84.24 6.345 ;
     RECT  2.16 6.615 84.24 6.885 ;
     RECT  2.16 7.155 84.24 7.425 ;
     RECT  2.16 7.695 84.24 7.965 ;
     RECT  2.16 8.235 84.24 8.505 ;
     RECT  2.16 8.775 84.24 9.045 ;
     RECT  2.16 9.315 84.24 9.585 ;
     RECT  2.16 9.855 84.24 10.125 ;
     RECT  2.16 10.395 84.24 10.665 ;
     RECT  2.16 10.935 84.24 11.205 ;
     RECT  2.16 11.475 84.24 11.745 ;
     RECT  2.16 12.015 84.24 12.285 ;
     RECT  2.16 12.555 84.24 12.825 ;
     RECT  2.16 13.095 84.24 13.365 ;
     RECT  2.16 13.635 84.24 13.905 ;
     RECT  2.16 14.175 84.24 14.445 ;
     RECT  2.16 14.715 84.24 14.985 ;
     RECT  2.16 15.255 84.24 15.525 ;
     RECT  2.16 15.795 84.24 16.065 ;
     RECT  2.16 16.335 84.24 16.605 ;
     RECT  2.16 16.875 84.24 17.145 ;
     RECT  2.16 17.415 84.24 17.685 ;
     RECT  2.16 17.955 84.24 18.225 ;
     RECT  2.16 18.495 84.24 18.765 ;
     RECT  2.16 19.035 84.24 19.305 ;
     RECT  2.16 19.575 84.24 19.845 ;
     RECT  2.16 20.115 84.24 20.385 ;
     RECT  2.16 20.655 84.24 20.925 ;
     RECT  2.16 21.195 84.24 21.465 ;
     RECT  2.16 21.735 84.24 22.005 ;
     RECT  2.16 22.275 84.24 22.545 ;
     RECT  2.16 22.815 84.24 23.085 ;
     RECT  2.16 23.355 84.24 23.625 ;
     RECT  2.16 23.895 84.24 24.165 ;
     RECT  2.16 24.435 84.24 24.705 ;
     RECT  2.16 24.975 84.24 25.245 ;
     RECT  2.16 25.515 84.24 25.785 ;
     RECT  2.16 26.055 84.24 26.325 ;
     RECT  2.16 26.595 84.24 26.865 ;
     RECT  2.16 27.135 84.24 27.405 ;
     RECT  2.16 27.675 84.24 27.945 ;
     RECT  2.16 28.215 84.24 28.485 ;
     RECT  2.16 28.755 84.24 29.025 ;
     RECT  2.16 29.295 84.24 29.565 ;
     RECT  2.16 29.835 84.24 30.105 ;
     RECT  2.16 30.375 84.24 30.645 ;
     RECT  2.16 30.915 84.24 31.185 ;
     RECT  2.16 31.455 84.24 31.725 ;
     RECT  2.16 31.995 84.24 32.265 ;
     RECT  2.16 32.535 84.24 32.805 ;
     RECT  2.16 33.075 84.24 33.345 ;
     RECT  2.16 33.615 84.24 33.885 ;
     RECT  2.16 34.155 84.24 34.425 ;
     RECT  2.16 34.695 84.24 34.965 ;
     RECT  2.16 35.235 84.24 35.505 ;
     RECT  2.16 35.775 84.24 36.045 ;
     RECT  2.16 36.315 84.24 36.585 ;
     RECT  2.16 36.855 84.24 37.125 ;
     RECT  2.16 37.395 84.24 37.665 ;
     RECT  2.16 37.935 84.24 38.205 ;
     RECT  2.16 38.475 84.24 38.745 ;
     RECT  2.16 39.015 84.24 39.285 ;
     RECT  2.16 39.555 84.24 39.825 ;
     RECT  2.16 40.095 84.24 40.365 ;
     RECT  2.16 40.635 84.24 40.905 ;
     RECT  2.16 41.175 84.24 41.445 ;
     RECT  2.16 41.715 84.24 41.985 ;
     RECT  2.16 42.255 84.24 42.525 ;
     RECT  2.16 42.795 84.24 43.065 ;
     RECT  2.16 43.335 84.24 43.605 ;
     RECT  2.16 43.875 84.24 44.145 ;
     RECT  2.16 44.415 84.24 44.685 ;
     RECT  2.16 44.955 84.24 45.225 ;
     RECT  2.16 45.495 84.24 45.765 ;
     RECT  2.16 46.035 84.24 46.305 ;
     RECT  2.16 46.575 84.24 46.845 ;
     RECT  2.16 47.115 84.24 47.385 ;
     RECT  2.16 47.655 84.24 47.925 ;
     RECT  2.16 48.195 84.24 48.465 ;
     RECT  2.16 48.735 84.24 49.005 ;
     RECT  2.16 49.275 84.24 49.545 ;
     RECT  2.16 49.815 84.24 50.085 ;
     RECT  2.16 50.355 84.24 50.625 ;
     RECT  2.16 50.895 84.24 51.165 ;
     RECT  2.16 51.435 84.24 51.705 ;
     RECT  2.16 51.975 84.24 52.245 ;
     RECT  2.16 52.515 84.24 52.785 ;
     RECT  2.16 53.055 84.24 53.325 ;
     RECT  2.16 53.595 84.24 53.865 ;
     RECT  2.16 54.135 84.24 54.405 ;
     RECT  2.16 54.675 84.24 54.945 ;
     RECT  2.16 55.215 84.24 55.485 ;
     RECT  2.16 55.755 84.24 56.025 ;
     RECT  2.16 56.295 84.24 56.565 ;
     RECT  2.16 56.835 84.24 57.105 ;
     RECT  2.16 57.375 84.24 57.645 ;
     RECT  2.16 57.915 84.24 58.185 ;
     RECT  2.16 58.455 84.24 58.725 ;
     RECT  2.16 58.995 84.24 59.265 ;
     RECT  2.16 59.535 84.24 59.805 ;
     RECT  2.16 60.075 84.24 60.345 ;
     RECT  2.16 60.615 84.24 60.885 ;
     RECT  2.16 61.155 84.24 61.425 ;
     RECT  2.16 61.695 84.24 61.965 ;
     RECT  2.16 62.235 84.24 62.505 ;
    LAYER M1 ;
     RECT  2.16 2.151 84.24 62.649 ;
    LAYER M2 ;
     RECT  0.103 36.36 0.139 36.378 ;
     RECT  0.103 25.56 0.175 25.578 ;
     RECT  0.103 26.532 0.175 26.55 ;
     RECT  0.139 27.342 0.175 27.36 ;
     RECT  0.103 28.458 0.175 28.818 ;
     RECT  0.103 31.626 0.203 31.644 ;
     RECT  0.139 30.654 0.211 30.672 ;
     RECT  0.211 30.654 0.247 30.708 ;
     RECT  0.175 25.56 0.463 26.55 ;
     RECT  0.175 27.342 0.463 28.818 ;
     RECT  0.463 25.56 0.535 28.818 ;
     RECT  0.103 29.88 0.535 29.898 ;
     RECT  0.247 30.654 0.535 31.248 ;
     RECT  1.147 34.776 1.723 34.794 ;
     RECT  1.723 34.434 1.759 34.794 ;
     RECT  0.535 25.29 2.16 28.818 ;
     RECT  0.535 29.88 2.16 31.248 ;
     RECT  1.759 34.236 2.16 34.794 ;
     RECT  0.139 36.09 2.16 36.378 ;
     RECT  2.16 2.151 84.24 62.649 ;
     RECT  84.24 29.034 84.911 38.574 ;
     RECT  84.911 35.046 85.055 38.574 ;
     RECT  84.24 40.536 85.199 40.824 ;
     RECT  84.911 29.034 85.415 34.074 ;
     RECT  85.415 29.034 85.451 33.264 ;
     RECT  85.055 35.046 85.451 38.124 ;
     RECT  85.451 29.34 85.487 33.066 ;
     RECT  85.415 34.056 85.487 34.074 ;
     RECT  85.451 35.046 85.487 37.854 ;
     RECT  84.24 27.216 85.523 27.36 ;
     RECT  85.487 31.536 85.523 31.914 ;
     RECT  85.487 36.864 85.523 36.882 ;
     RECT  85.523 27.342 86.315 27.36 ;
     RECT  85.487 29.502 86.315 30.744 ;
     RECT  85.487 33.048 86.315 33.066 ;
     RECT  84.24 39.528 86.315 39.546 ;
     RECT  86.287 37.908 86.387 37.926 ;
     RECT  85.199 40.536 86.387 40.554 ;
    LAYER M3 ;
     RECT  2.415 2.143 2.505 2.413 ;
     RECT  7.815 2.143 7.905 2.413 ;
     RECT  13.215 2.143 13.305 2.413 ;
     RECT  18.615 2.143 18.705 2.413 ;
     RECT  24.015 2.143 24.105 2.413 ;
     RECT  29.415 2.143 29.505 2.413 ;
     RECT  34.815 2.143 34.905 2.413 ;
     RECT  40.215 2.143 40.305 2.413 ;
     RECT  45.615 2.143 45.705 2.413 ;
     RECT  51.015 2.143 51.105 2.413 ;
     RECT  56.415 2.143 56.505 2.413 ;
     RECT  61.815 2.143 61.905 2.413 ;
     RECT  67.215 2.143 67.305 2.413 ;
     RECT  72.615 2.143 72.705 2.413 ;
     RECT  78.015 2.143 78.105 2.413 ;
     RECT  83.415 2.143 83.505 2.413 ;
     RECT  2.415 2.413 2.697 24.745 ;
     RECT  2.376 24.745 2.697 24.781 ;
     RECT  2.376 24.781 3.546 24.943 ;
     RECT  4.464 24.637 4.482 24.943 ;
     RECT  2.376 24.943 4.482 25.015 ;
     RECT  6.912 24.979 6.93 25.051 ;
     RECT  6.912 25.051 6.966 25.177 ;
     RECT  7.815 2.413 8.097 25.177 ;
     RECT  0.54 25.285 0.558 25.555 ;
     RECT  2.304 25.015 4.914 26.059 ;
     RECT  2.304 26.059 5.562 26.131 ;
     RECT  83.415 2.413 83.697 26.131 ;
     RECT  40.215 2.413 40.497 26.221 ;
     RECT  82.44 26.131 82.458 26.365 ;
     RECT  83.304 26.131 83.697 26.365 ;
     RECT  6.912 25.177 8.097 26.491 ;
     RECT  9.108 26.329 9.126 26.491 ;
     RECT  2.304 26.131 5.778 26.563 ;
     RECT  6.912 26.491 9.126 26.563 ;
     RECT  82.44 26.365 83.697 26.599 ;
     RECT  82.44 26.599 84.15 26.635 ;
     RECT  46.764 25.681 46.782 26.671 ;
     RECT  48.456 26.563 48.474 26.761 ;
     RECT  2.304 26.563 9.126 26.789 ;
     RECT  82.224 26.635 84.15 26.941 ;
     RECT  44.532 26.635 44.55 27.031 ;
     RECT  45.615 2.413 45.897 27.031 ;
     RECT  40.215 26.221 40.734 27.103 ;
     RECT  6.156 26.789 9.126 27.104 ;
     RECT  44.532 27.031 45.897 27.211 ;
     RECT  46.764 26.671 47.178 27.211 ;
     RECT  81.216 26.671 81.234 27.211 ;
     RECT  81.972 26.941 84.15 27.211 ;
     RECT  9.036 27.104 9.126 27.239 ;
     RECT  10.764 27.103 10.782 27.329 ;
     RECT  44.532 27.211 47.178 27.337 ;
     RECT  48.456 26.761 49.158 27.337 ;
     RECT  80.388 27.301 80.406 27.679 ;
     RECT  44.532 27.337 49.158 27.715 ;
     RECT  6.156 27.104 8.298 27.751 ;
     RECT  41.868 26.599 41.886 27.751 ;
     RECT  43.884 27.715 49.158 27.751 ;
     RECT  6.12 27.751 8.298 27.869 ;
     RECT  9.036 27.239 9.054 27.869 ;
     RECT  2.304 26.789 5.382 27.877 ;
     RECT  6.12 27.869 8.154 27.877 ;
     RECT  2.304 27.877 8.154 27.905 ;
     RECT  7.776 27.905 8.154 27.917 ;
     RECT  43.884 27.751 49.59 27.985 ;
     RECT  51.015 2.413 51.297 28.021 ;
     RECT  2.304 27.905 6.93 28.139 ;
     RECT  40.215 27.103 41.022 28.147 ;
     RECT  41.868 27.751 42.318 28.147 ;
     RECT  0.108 25.555 0.558 28.205 ;
     RECT  43.884 27.985 49.698 28.219 ;
     RECT  51.015 28.021 51.426 28.219 ;
     RECT  0.108 28.205 0.522 28.397 ;
     RECT  39.024 26.329 39.042 28.489 ;
     RECT  40.215 28.147 42.318 28.489 ;
     RECT  40.215 28.489 43.038 28.517 ;
     RECT  78.015 2.413 78.297 28.525 ;
     RECT  81.216 27.211 84.15 28.589 ;
     RECT  37.944 28.219 37.962 28.679 ;
     RECT  7.776 27.917 8.097 28.715 ;
     RECT  41.616 28.517 43.038 28.759 ;
     RECT  43.884 28.219 51.426 28.759 ;
     RECT  0.108 28.397 0.342 28.781 ;
     RECT  41.616 28.759 51.426 28.795 ;
     RECT  38.772 28.489 39.042 28.823 ;
     RECT  41.616 28.795 51.57 28.831 ;
     RECT  52.668 28.561 52.758 28.831 ;
     RECT  2.304 28.139 4.662 28.921 ;
     RECT  5.508 28.139 6.93 28.921 ;
     RECT  40.215 28.517 40.734 28.949 ;
     RECT  38.772 28.823 38.79 29.021 ;
     RECT  41.616 28.831 52.758 29.021 ;
     RECT  85.5 27.211 85.518 29.029 ;
     RECT  0.108 28.781 0.27 29.069 ;
     RECT  41.616 29.021 52.038 29.219 ;
     RECT  9.108 28.561 9.126 29.291 ;
     RECT  80.388 27.679 80.442 29.291 ;
     RECT  78.015 28.525 78.678 29.299 ;
     RECT  2.304 28.921 6.93 29.335 ;
     RECT  7.815 28.715 8.097 29.335 ;
     RECT  52.812 29.101 52.866 29.335 ;
     RECT  80.424 29.291 80.442 29.363 ;
     RECT  81.288 28.589 84.15 29.371 ;
     RECT  78.015 29.299 78.75 29.399 ;
     RECT  2.304 29.335 7.074 29.405 ;
     RECT  85.428 29.029 85.518 29.453 ;
     RECT  2.304 29.405 6.534 29.489 ;
     RECT  50.58 29.219 52.038 29.489 ;
     RECT  52.812 29.335 52.938 29.489 ;
     RECT  52.884 29.489 52.938 29.512 ;
     RECT  81.18 29.371 84.15 29.515 ;
     RECT  50.58 29.489 51.678 29.525 ;
     RECT  41.616 29.219 49.734 29.561 ;
     RECT  50.724 29.525 51.678 29.597 ;
     RECT  52.884 29.512 52.902 29.597 ;
     RECT  81.18 29.515 84.366 29.605 ;
     RECT  85.428 29.453 85.482 29.605 ;
     RECT  2.304 29.489 5.706 29.633 ;
     RECT  81.18 29.605 85.482 29.767 ;
     RECT  2.304 29.633 5.67 29.789 ;
     RECT  2.304 29.789 4.302 29.795 ;
     RECT  41.616 29.561 46.782 29.795 ;
     RECT  7.815 29.335 8.154 29.911 ;
     RECT  0.108 29.069 0.126 30.001 ;
     RECT  47.52 29.561 49.734 30.001 ;
     RECT  7.488 29.911 8.154 30.029 ;
     RECT  47.52 30.001 49.806 30.136 ;
     RECT  6.516 29.489 6.534 30.271 ;
     RECT  7.815 30.029 8.154 30.307 ;
     RECT  78.015 29.399 78.297 30.307 ;
     RECT  86.292 27.337 86.31 30.307 ;
     RECT  80.964 29.767 85.482 30.407 ;
     RECT  41.688 29.795 46.782 30.415 ;
     RECT  47.52 30.136 49.986 30.415 ;
     RECT  5.184 29.789 5.67 30.451 ;
     RECT  6.516 30.271 7.002 30.451 ;
     RECT  41.688 30.415 49.986 30.451 ;
     RECT  50.724 29.597 51.297 30.451 ;
     RECT  80.964 30.407 80.982 30.451 ;
     RECT  80.64 30.451 80.982 30.479 ;
     RECT  78.015 30.307 78.678 30.569 ;
     RECT  2.34 29.795 4.302 30.577 ;
     RECT  5.184 30.451 7.002 30.577 ;
     RECT  0.108 30.001 0.558 30.605 ;
     RECT  41.688 30.451 51.462 30.605 ;
     RECT  40.215 28.949 40.497 30.649 ;
     RECT  41.688 30.605 49.662 30.649 ;
     RECT  81.72 30.407 85.482 30.685 ;
     RECT  40.215 30.649 49.662 30.749 ;
     RECT  86.256 30.307 86.31 30.797 ;
     RECT  2.34 30.577 7.002 30.839 ;
     RECT  40.215 30.749 40.497 30.847 ;
     RECT  86.292 30.797 86.31 30.893 ;
     RECT  79.884 30.343 79.902 31.019 ;
     RECT  50.4 30.605 51.462 31.109 ;
     RECT  81.72 30.685 85.518 31.181 ;
     RECT  2.34 30.839 6.858 31.217 ;
     RECT  2.34 31.217 6.822 31.243 ;
     RECT  50.724 31.109 51.462 31.261 ;
     RECT  78.015 30.569 78.297 31.351 ;
     RECT  52.488 31.081 52.506 31.379 ;
     RECT  0.108 30.605 0.27 31.469 ;
     RECT  78.015 31.351 78.75 31.487 ;
     RECT  39.924 30.847 40.497 31.495 ;
     RECT  41.688 30.749 49.662 31.495 ;
     RECT  7.815 30.307 8.19 31.531 ;
     RECT  39.924 31.495 49.662 31.531 ;
     RECT  80.64 30.479 80.838 31.531 ;
     RECT  81.72 31.181 84.006 31.531 ;
     RECT  50.724 31.261 51.498 31.559 ;
     RECT  0.108 31.469 0.234 31.565 ;
     RECT  52.308 31.423 52.398 31.621 ;
     RECT  0.108 31.565 0.198 31.649 ;
     RECT  80.64 31.531 84.006 31.729 ;
     RECT  39.924 31.531 49.698 31.757 ;
     RECT  7.815 31.531 8.514 31.765 ;
     RECT  9.36 31.495 9.378 31.801 ;
     RECT  38.772 30.991 38.79 31.801 ;
     RECT  52.02 31.621 52.398 31.829 ;
     RECT  0.144 31.649 0.162 31.853 ;
     RECT  7.776 31.765 8.514 31.919 ;
     RECT  9.288 31.801 9.378 31.919 ;
     RECT  50.724 31.559 51.297 31.919 ;
     RECT  52.38 31.829 52.398 31.919 ;
     RECT  39.924 31.757 49.194 31.955 ;
     RECT  38.772 31.801 38.862 31.963 ;
     RECT  39.924 31.955 47.574 31.963 ;
     RECT  2.304 31.243 6.822 32.011 ;
     RECT  80.604 31.729 84.006 32.071 ;
     RECT  84.816 31.181 85.518 32.071 ;
     RECT  80.604 32.071 85.518 32.189 ;
     RECT  9.324 31.919 9.378 32.197 ;
     RECT  80.964 32.189 85.518 32.237 ;
     RECT  38.772 31.963 47.574 32.333 ;
     RECT  9.324 32.197 9.486 32.342 ;
     RECT  2.304 32.011 6.93 32.395 ;
     RECT  7.815 31.919 8.514 32.459 ;
     RECT  9.36 32.342 9.486 32.459 ;
     RECT  80.964 32.237 85.482 32.621 ;
     RECT  9.432 32.459 9.486 32.639 ;
     RECT  38.808 32.333 47.574 32.683 ;
     RECT  48.348 31.955 49.194 32.683 ;
     RECT  79.236 32.197 79.254 32.729 ;
     RECT  7.815 32.459 8.19 32.845 ;
     RECT  38.808 32.683 49.194 32.873 ;
     RECT  2.232 32.395 6.93 32.881 ;
     RECT  10.728 32.503 10.746 32.881 ;
     RECT  84.816 32.621 85.482 32.909 ;
     RECT  1.152 32.971 1.17 33.067 ;
     RECT  2.232 32.881 6.966 33.067 ;
     RECT  38.844 32.873 49.194 33.079 ;
     RECT  10.728 32.881 10.818 33.115 ;
     RECT  34.815 2.413 35.097 33.115 ;
     RECT  10.62 33.115 10.818 33.151 ;
     RECT  38.844 33.079 49.878 33.179 ;
     RECT  1.152 33.067 6.966 33.241 ;
     RECT  7.74 32.845 8.19 33.241 ;
     RECT  1.152 33.241 8.37 33.277 ;
     RECT  86.292 33.043 86.31 33.293 ;
     RECT  10.476 33.151 10.818 33.307 ;
     RECT  10.476 33.307 10.89 33.349 ;
     RECT  78.015 31.487 78.297 33.349 ;
     RECT  9.648 32.965 9.666 33.385 ;
     RECT  10.44 33.349 10.89 33.385 ;
     RECT  1.152 33.277 8.91 33.421 ;
     RECT  9.648 33.385 10.89 33.421 ;
     RECT  80.964 32.621 83.934 33.421 ;
     RECT  1.152 33.421 10.89 33.437 ;
     RECT  22.824 33.307 22.842 33.437 ;
     RECT  30.78 33.307 30.798 33.437 ;
     RECT  38.844 33.179 49.842 33.611 ;
     RECT  79.56 33.307 79.578 33.611 ;
     RECT  80.856 33.421 83.934 33.619 ;
     RECT  1.152 33.437 10.854 33.629 ;
     RECT  80.388 33.619 83.934 33.677 ;
     RECT  38.844 33.611 49.302 33.691 ;
     RECT  10.836 33.629 10.854 33.821 ;
     RECT  0.324 33.739 0.342 33.835 ;
     RECT  0.18 33.835 0.342 33.869 ;
     RECT  34.776 33.115 35.097 33.917 ;
     RECT  78.015 33.349 78.678 33.953 ;
     RECT  80.532 33.677 83.934 33.989 ;
     RECT  80.532 33.989 80.73 34.079 ;
     RECT  84.852 32.909 85.482 34.079 ;
     RECT  0.18 33.869 0.234 34.109 ;
     RECT  80.532 34.079 80.658 34.115 ;
     RECT  51.015 31.919 51.297 34.195 ;
     RECT  0.18 34.109 0.198 34.205 ;
     RECT  50.868 34.195 51.297 34.393 ;
     RECT  1.152 33.629 9.954 34.457 ;
     RECT  38.772 33.691 49.302 34.457 ;
     RECT  40.215 34.457 49.302 34.465 ;
     RECT  78.015 33.953 78.297 34.501 ;
     RECT  2.268 34.457 9.954 34.591 ;
     RECT  2.268 34.591 10.242 34.619 ;
     RECT  84.852 34.079 84.906 34.619 ;
     RECT  10.224 34.619 10.242 34.627 ;
     RECT  10.224 34.627 10.854 34.637 ;
     RECT  38.772 34.457 39.366 34.655 ;
     RECT  50.652 34.393 51.297 34.691 ;
     RECT  0.144 34.315 0.162 34.733 ;
     RECT  2.268 34.619 9.486 34.781 ;
     RECT  1.152 34.457 1.17 34.799 ;
     RECT  80.64 34.115 80.658 34.861 ;
     RECT  6.912 34.781 9.486 34.889 ;
     RECT  2.268 34.781 5.742 34.925 ;
     RECT  77.544 34.501 78.297 34.933 ;
     RECT  40.215 34.465 49.554 34.982 ;
     RECT  8.856 34.889 9.486 34.997 ;
     RECT  10.512 34.637 10.854 35.041 ;
     RECT  8.856 34.997 9.378 35.069 ;
     RECT  77.544 34.933 78.75 35.069 ;
     RECT  50.796 34.691 51.297 35.159 ;
     RECT  10.512 35.041 11.394 35.195 ;
     RECT  39.348 34.655 39.366 35.239 ;
     RECT  40.215 34.982 49.698 35.239 ;
     RECT  39.348 35.239 49.698 35.267 ;
     RECT  80.64 34.861 80.73 35.311 ;
     RECT  81.468 33.989 83.934 35.311 ;
     RECT  9.108 35.069 9.378 35.357 ;
     RECT  2.304 34.925 5.742 35.429 ;
     RECT  77.544 35.069 78.297 35.429 ;
     RECT  85.464 35.041 85.482 35.467 ;
     RECT  5.724 35.429 5.742 35.501 ;
     RECT  80.64 35.311 83.934 35.501 ;
     RECT  10.512 35.195 10.746 35.537 ;
     RECT  80.64 35.501 83.79 35.537 ;
     RECT  84.888 35.467 85.482 35.563 ;
     RECT  80.64 35.537 83.754 35.581 ;
     RECT  6.912 34.889 8.097 35.609 ;
     RECT  84.852 35.563 85.482 35.659 ;
     RECT  10.728 35.537 10.746 35.699 ;
     RECT  39.708 35.267 49.698 35.699 ;
     RECT  2.304 35.429 4.806 35.735 ;
     RECT  39.708 35.699 41.958 35.735 ;
     RECT  45.468 35.699 49.698 35.735 ;
     RECT  39.816 35.735 41.958 35.771 ;
     RECT  39.888 35.771 41.958 35.807 ;
     RECT  79.236 35.581 79.326 35.807 ;
     RECT  40.215 35.807 41.958 35.885 ;
     RECT  9.36 35.357 9.378 35.899 ;
     RECT  45.576 35.735 49.698 35.941 ;
     RECT  84.816 35.659 85.482 35.947 ;
     RECT  9.36 35.899 9.702 35.969 ;
     RECT  78.015 35.429 78.297 35.977 ;
     RECT  79.236 35.807 79.254 35.977 ;
     RECT  9.36 35.969 9.414 36.085 ;
     RECT  80.568 35.581 83.754 36.121 ;
     RECT  7.092 35.609 8.097 36.149 ;
     RECT  45.576 35.941 49.734 36.187 ;
     RECT  2.415 35.735 4.806 36.239 ;
     RECT  9.108 36.085 9.414 36.239 ;
     RECT  78.015 35.977 79.254 36.239 ;
     RECT  45.576 36.187 49.914 36.269 ;
     RECT  0.144 36.085 0.162 36.355 ;
     RECT  9.108 36.239 9.126 36.365 ;
     RECT  49.428 36.269 49.914 36.379 ;
     RECT  49.428 36.379 49.95 36.392 ;
     RECT  49.464 36.392 49.95 36.509 ;
     RECT  80.388 36.121 83.754 36.523 ;
     RECT  84.816 35.947 85.518 36.523 ;
     RECT  50.832 35.159 51.297 36.589 ;
     RECT  2.415 36.239 3.438 36.625 ;
     RECT  40.215 35.885 41.922 36.625 ;
     RECT  0.108 36.355 0.162 36.653 ;
     RECT  4.176 36.239 4.806 36.661 ;
     RECT  39.78 36.625 41.958 36.661 ;
     RECT  42.804 35.699 44.694 36.661 ;
     RECT  50.508 36.589 51.297 36.689 ;
     RECT  0.144 36.653 0.162 36.749 ;
     RECT  5.688 36.625 5.706 36.779 ;
     RECT  39.78 36.661 44.694 36.779 ;
     RECT  78.015 36.239 78.786 36.779 ;
     RECT  42.876 36.779 44.694 36.859 ;
     RECT  45.576 36.269 48.69 36.859 ;
     RECT  50.58 36.689 51.297 36.887 ;
     RECT  80.388 36.523 85.518 36.887 ;
     RECT  10.8 36.787 10.818 36.923 ;
     RECT  6.624 36.553 6.642 36.931 ;
     RECT  7.452 36.149 8.097 36.931 ;
     RECT  39.78 36.779 42.102 36.931 ;
     RECT  42.876 36.859 48.69 36.959 ;
     RECT  4.176 36.661 4.914 36.989 ;
     RECT  6.48 36.931 8.097 36.989 ;
     RECT  2.304 36.625 3.438 37.003 ;
     RECT  4.176 36.989 4.554 37.003 ;
     RECT  2.304 37.003 4.554 37.049 ;
     RECT  10.872 36.931 10.89 37.049 ;
     RECT  39.708 36.931 42.102 37.049 ;
     RECT  42.876 36.959 47.106 37.049 ;
     RECT  48.06 36.959 48.69 37.049 ;
     RECT  49.608 36.509 49.77 37.049 ;
     RECT  78.015 36.779 78.75 37.049 ;
     RECT  48.312 37.049 48.69 37.085 ;
     RECT  2.304 37.049 2.697 37.133 ;
     RECT  39.924 37.049 42.102 37.157 ;
     RECT  48.348 37.085 48.69 37.157 ;
     RECT  3.42 37.049 4.554 37.319 ;
     RECT  5.4 37.165 5.418 37.319 ;
     RECT  40.104 37.157 42.102 37.319 ;
     RECT  42.876 37.049 46.818 37.319 ;
     RECT  48.852 37.201 48.87 37.319 ;
     RECT  3.96 37.319 4.554 37.355 ;
     RECT  6.84 36.989 8.097 37.355 ;
     RECT  40.104 37.319 41.958 37.355 ;
     RECT  80.388 36.887 85.482 37.391 ;
     RECT  42.876 37.319 44.838 37.499 ;
     RECT  45.576 37.319 46.242 37.499 ;
     RECT  81.072 37.391 85.482 37.517 ;
     RECT  45.615 37.499 46.242 37.589 ;
     RECT  78.015 37.049 78.714 37.589 ;
     RECT  40.215 37.355 41.922 37.625 ;
     RECT  49.608 37.049 49.626 37.625 ;
     RECT  81.072 37.517 84.114 37.769 ;
     RECT  84.852 37.517 85.482 37.859 ;
     RECT  44.82 37.499 44.838 37.895 ;
     RECT  86.292 37.867 86.31 37.903 ;
     RECT  7.2 37.355 8.097 38.129 ;
     RECT  84.852 37.859 85.446 38.129 ;
     RECT  37.836 28.795 37.854 38.209 ;
     RECT  40.215 37.625 40.842 38.309 ;
     RECT  3.96 37.355 4.194 38.347 ;
     RECT  84.852 38.129 85.194 38.399 ;
     RECT  3.96 38.347 4.338 38.515 ;
     RECT  81.072 37.769 83.934 38.515 ;
     RECT  18.615 2.413 18.897 38.551 ;
     RECT  85.032 38.399 85.194 38.579 ;
     RECT  3.816 38.515 4.338 38.669 ;
     RECT  18.615 38.551 19.134 38.669 ;
     RECT  3.996 38.669 4.338 38.705 ;
     RECT  37.836 38.209 38.178 38.705 ;
     RECT  81.072 38.515 83.97 38.705 ;
     RECT  10.836 38.539 10.854 38.717 ;
     RECT  15.948 38.677 15.966 38.717 ;
     RECT  38.016 38.705 38.178 38.741 ;
     RECT  41.904 37.625 41.922 38.749 ;
     RECT  41.652 38.749 41.922 38.777 ;
     RECT  2.34 37.133 2.697 38.779 ;
     RECT  38.16 38.741 38.178 38.779 ;
     RECT  38.16 38.779 38.322 38.821 ;
     RECT  39.168 38.713 39.186 38.821 ;
     RECT  81.18 38.705 83.97 38.939 ;
     RECT  2.304 38.779 2.697 38.975 ;
     RECT  38.16 38.821 39.186 39.083 ;
     RECT  42.876 37.499 44.082 39.163 ;
     RECT  4.176 38.705 4.338 39.209 ;
     RECT  5.112 39.181 5.13 39.245 ;
     RECT  38.16 39.083 38.898 39.245 ;
     RECT  42.444 39.163 44.082 39.251 ;
     RECT  86.292 37.903 86.382 39.551 ;
     RECT  81.216 38.939 83.97 39.749 ;
     RECT  81.216 39.749 83.934 40.199 ;
     RECT  77.22 36.283 77.238 40.559 ;
     RECT  81.9 40.199 83.934 40.559 ;
     RECT  86.364 39.551 86.382 40.559 ;
     RECT  85.176 38.579 85.194 40.829 ;
     RECT  81.972 40.559 83.934 41.099 ;
     RECT  82.368 41.099 83.697 41.171 ;
     RECT  82.476 41.171 83.697 41.405 ;
     RECT  82.476 41.405 82.602 41.639 ;
     RECT  82.476 41.639 82.494 41.819 ;
     RECT  28.08 42.763 28.098 43.051 ;
     RECT  27.72 43.051 28.098 43.259 ;
     RECT  41.652 38.777 41.67 51.307 ;
     RECT  41.436 51.307 41.67 51.629 ;
     RECT  41.472 51.629 41.67 52.013 ;
     RECT  42.876 39.251 44.082 53.051 ;
     RECT  42.948 53.051 44.082 54.811 ;
     RECT  42.948 54.811 44.766 54.955 ;
     RECT  45.615 37.589 45.897 54.955 ;
     RECT  42.948 54.955 45.897 55.021 ;
     RECT  42.948 55.021 46.026 55.139 ;
     RECT  42.948 55.139 45.897 55.915 ;
     RECT  42.768 55.915 45.897 55.921 ;
     RECT  42.768 55.921 45.99 55.957 ;
     RECT  46.908 55.957 46.926 55.993 ;
     RECT  41.652 52.013 41.67 56.029 ;
     RECT  41.616 56.029 41.67 56.065 ;
     RECT  42.768 55.957 46.098 56.065 ;
     RECT  46.872 55.993 46.926 56.101 ;
     RECT  41.616 56.065 46.098 56.251 ;
     RECT  39.06 56.251 39.078 56.291 ;
     RECT  40.215 38.309 40.497 56.299 ;
     RECT  46.872 56.101 47.394 56.327 ;
     RECT  40.032 56.299 40.497 56.335 ;
     RECT  39.852 56.335 40.497 56.371 ;
     RECT  39.204 56.371 40.497 56.489 ;
     RECT  38.16 39.245 38.178 56.597 ;
     RECT  39.924 56.489 40.497 56.597 ;
     RECT  40.104 56.597 40.497 56.605 ;
     RECT  40.104 56.605 40.626 56.831 ;
     RECT  41.436 56.251 46.098 56.911 ;
     RECT  46.872 56.327 47.07 56.911 ;
     RECT  40.215 56.831 40.626 57.001 ;
     RECT  41.436 56.911 47.07 57.001 ;
     RECT  40.215 57.001 47.07 57.181 ;
     RECT  40.215 57.181 47.538 57.299 ;
     RECT  41.544 57.299 47.538 57.407 ;
     RECT  41.544 57.407 46.89 57.479 ;
     RECT  41.544 57.479 41.634 57.569 ;
     RECT  40.215 57.299 40.77 57.581 ;
     RECT  4.176 39.209 4.194 57.605 ;
     RECT  42.408 57.479 46.89 57.629 ;
     RECT  40.215 57.581 40.626 57.641 ;
     RECT  42.408 57.629 46.17 57.869 ;
     RECT  41.616 57.569 41.634 58.531 ;
     RECT  42.408 57.869 45.897 58.531 ;
     RECT  41.616 58.531 45.897 58.621 ;
     RECT  41.544 58.621 45.897 58.733 ;
     RECT  42.264 58.733 45.897 59.261 ;
     RECT  42.408 59.261 45.897 60.079 ;
     RECT  40.215 57.641 40.497 60.151 ;
     RECT  42.012 60.079 45.897 60.151 ;
     RECT  40.215 60.151 46.458 60.269 ;
     RECT  40.215 60.269 45.99 60.305 ;
     RECT  41.652 60.305 45.99 60.575 ;
     RECT  41.652 60.575 45.897 60.809 ;
     RECT  42.084 60.809 45.897 60.845 ;
     RECT  42.084 60.845 44.802 61.663 ;
     RECT  42.084 61.663 44.874 62.069 ;
     RECT  42.84 62.069 44.874 62.275 ;
     RECT  45.615 60.845 45.897 62.275 ;
     RECT  2.415 38.975 2.697 62.387 ;
     RECT  7.815 38.129 8.097 62.387 ;
     RECT  13.215 2.413 13.497 62.387 ;
     RECT  18.615 38.669 18.897 62.387 ;
     RECT  24.015 2.413 24.297 62.387 ;
     RECT  29.415 2.413 29.697 62.387 ;
     RECT  34.815 33.917 35.097 62.387 ;
     RECT  40.215 60.305 40.497 62.387 ;
     RECT  42.84 62.275 45.897 62.387 ;
     RECT  51.015 36.887 51.297 62.387 ;
     RECT  56.415 2.413 56.697 62.387 ;
     RECT  61.815 2.413 62.097 62.387 ;
     RECT  67.215 2.413 67.497 62.387 ;
     RECT  72.615 2.413 72.897 62.387 ;
     RECT  78.015 37.589 78.297 62.387 ;
     RECT  83.415 41.405 83.697 62.387 ;
     RECT  42.084 62.069 42.102 62.429 ;
     RECT  2.415 62.387 2.505 62.657 ;
     RECT  7.815 62.387 7.905 62.657 ;
     RECT  13.215 62.387 13.305 62.657 ;
     RECT  18.615 62.387 18.705 62.657 ;
     RECT  24.015 62.387 24.105 62.657 ;
     RECT  29.415 62.387 29.505 62.657 ;
     RECT  34.815 62.387 34.905 62.657 ;
     RECT  40.215 62.387 40.305 62.657 ;
     RECT  42.84 62.387 45.705 62.657 ;
     RECT  51.015 62.387 51.105 62.657 ;
     RECT  56.415 62.387 56.505 62.657 ;
     RECT  61.815 62.387 61.905 62.657 ;
     RECT  67.215 62.387 67.305 62.657 ;
     RECT  72.615 62.387 72.705 62.657 ;
     RECT  78.015 62.387 78.105 62.657 ;
     RECT  83.415 62.387 83.505 62.657 ;
     RECT  42.84 62.657 45.162 62.765 ;
     RECT  45.144 62.765 45.162 62.861 ;
     RECT  42.84 62.765 44.334 63.293 ;
     RECT  42.84 63.293 43.83 63.917 ;
     RECT  43.164 63.917 43.182 63.965 ;
     RECT  44.964 64.507 44.982 64.685 ;
    LAYER M4 ;
     RECT  0.06 26.448 0.133 34.344 ;
     RECT  0.133 26.448 0.137 34.728 ;
     RECT  0.06 36.624 0.137 37.128 ;
     RECT  0.137 36.72 0.173 37.128 ;
     RECT  0.06 38.544 0.277 38.664 ;
     RECT  0.137 26.544 0.569 34.728 ;
     RECT  0.569 26.64 2.408 34.728 ;
     RECT  0.173 36.816 2.408 37.128 ;
     RECT  0.277 38.544 2.408 38.808 ;
     RECT  0.181 43.056 2.408 43.08 ;
     RECT  2.408 2.148 2.512 62.652 ;
     RECT  2.512 2.418 2.704 62.382 ;
     RECT  2.704 29.232 2.765 29.256 ;
     RECT  2.704 30.384 2.837 33.864 ;
     RECT  2.704 36.912 2.837 37.032 ;
     RECT  2.837 30.384 2.945 32.808 ;
     RECT  2.704 27.984 3.125 28.248 ;
     RECT  2.945 30.384 3.125 31.704 ;
     RECT  2.837 33.84 3.125 33.864 ;
     RECT  2.945 32.784 3.161 32.808 ;
     RECT  3.125 28.128 3.769 28.248 ;
     RECT  2.704 38.544 4.309 38.568 ;
     RECT  3.125 30.384 4.349 31.416 ;
     RECT  3.769 28.128 4.357 29.016 ;
     RECT  4.349 30.384 4.357 30.744 ;
     RECT  4.357 28.128 4.403 30.744 ;
     RECT  4.129 34.128 4.405 34.152 ;
     RECT  4.309 38.352 4.451 38.568 ;
     RECT  4.309 26.688 4.453 26.712 ;
     RECT  4.453 32.496 4.501 32.52 ;
     RECT  4.405 34.128 4.501 34.776 ;
     RECT  4.501 32.496 4.525 34.776 ;
     RECT  2.837 37.008 4.565 37.032 ;
     RECT  4.525 32.16 4.595 34.776 ;
     RECT  4.453 26.688 4.741 26.76 ;
     RECT  4.741 26.208 5.077 26.76 ;
     RECT  4.403 28.128 5.077 30.696 ;
     RECT  4.451 38.544 5.101 38.568 ;
     RECT  5.077 26.208 5.429 30.696 ;
     RECT  5.429 27.216 5.461 30.696 ;
     RECT  5.461 27.216 5.497 30.936 ;
     RECT  4.595 32.16 5.497 33.768 ;
     RECT  5.497 27.216 5.605 33.768 ;
     RECT  4.595 34.752 5.605 34.776 ;
     RECT  5.605 27.216 5.645 34.776 ;
     RECT  5.645 27.216 6.049 32.76 ;
     RECT  6.049 30.816 6.785 32.76 ;
     RECT  5.645 33.744 6.785 34.776 ;
     RECT  4.741 36.96 6.829 36.984 ;
     RECT  6.049 27.216 6.937 29.784 ;
     RECT  6.785 30.816 7.093 34.776 ;
     RECT  6.937 27.072 7.808 29.784 ;
     RECT  7.093 30.816 7.808 34.92 ;
     RECT  6.829 36.96 7.808 37.08 ;
     RECT  5.101 38.544 7.808 39.24 ;
     RECT  2.704 43.056 7.808 43.08 ;
     RECT  7.808 2.148 7.912 62.652 ;
     RECT  7.912 2.418 8.104 62.382 ;
     RECT  8.104 27.072 8.165 28.248 ;
     RECT  8.104 29.616 8.243 29.784 ;
     RECT  8.165 27.072 8.381 27.096 ;
     RECT  8.243 29.76 8.387 29.784 ;
     RECT  8.104 30.912 8.425 36.216 ;
     RECT  8.425 32.736 9.068 36.216 ;
     RECT  8.104 38.544 9.109 39.24 ;
     RECT  9.068 32.736 9.148 36.36 ;
     RECT  9.148 35.904 9.155 36.36 ;
     RECT  9.155 35.904 9.425 36.216 ;
     RECT  9.148 32.736 9.731 34.632 ;
     RECT  9.425 35.904 9.757 35.928 ;
     RECT  8.425 30.912 10.307 31.176 ;
     RECT  9.731 33.168 10.463 34.632 ;
     RECT  10.307 30.912 10.547 30.936 ;
     RECT  10.463 33.168 10.685 35.352 ;
     RECT  10.685 33.216 10.829 35.352 ;
     RECT  10.829 33.312 10.835 35.352 ;
     RECT  10.835 33.312 10.865 33.816 ;
     RECT  10.835 35.088 10.865 35.112 ;
     RECT  10.865 33.312 10.901 33.432 ;
     RECT  8.165 28.224 13.208 28.248 ;
     RECT  10.901 33.312 13.208 33.336 ;
     RECT  9.109 37.92 13.208 39.24 ;
     RECT  8.104 43.056 13.208 43.08 ;
     RECT  13.208 2.148 13.312 62.652 ;
     RECT  13.312 2.418 13.504 62.382 ;
     RECT  13.504 37.92 15.977 39.24 ;
     RECT  13.504 28.224 18.608 28.248 ;
     RECT  13.504 33.408 18.608 33.432 ;
     RECT  15.977 37.92 18.608 37.944 ;
     RECT  15.977 39.216 18.608 39.24 ;
     RECT  13.504 43.056 18.608 43.08 ;
     RECT  18.608 2.148 18.712 62.652 ;
     RECT  18.712 2.418 18.904 62.382 ;
     RECT  18.904 33.408 22.813 33.432 ;
     RECT  22.813 33.312 22.853 33.432 ;
     RECT  18.904 28.224 24.008 28.248 ;
     RECT  22.853 33.312 24.008 33.336 ;
     RECT  18.904 37.92 24.008 37.944 ;
     RECT  18.904 39.216 24.008 39.24 ;
     RECT  18.904 43.056 24.008 43.08 ;
     RECT  24.008 2.148 24.112 62.652 ;
     RECT  24.112 2.418 24.304 62.382 ;
     RECT  24.304 43.056 27.749 43.08 ;
     RECT  28.069 42.768 28.153 42.792 ;
     RECT  24.304 28.224 29.408 28.248 ;
     RECT  24.304 33.408 29.408 33.432 ;
     RECT  24.304 37.92 29.408 37.944 ;
     RECT  24.304 39.216 29.408 39.24 ;
     RECT  29.408 2.148 29.512 62.652 ;
     RECT  29.512 2.418 29.704 62.382 ;
     RECT  29.704 33.408 30.769 33.432 ;
     RECT  30.769 33.312 30.809 33.432 ;
     RECT  30.809 33.312 34.765 33.336 ;
     RECT  29.704 28.224 34.808 28.248 ;
     RECT  34.765 33.12 34.808 33.336 ;
     RECT  29.704 37.92 34.808 37.944 ;
     RECT  29.704 39.216 34.808 39.24 ;
     RECT  34.808 2.148 34.912 62.652 ;
     RECT  34.912 2.418 35.104 62.382 ;
     RECT  35.104 28.224 37.973 28.248 ;
     RECT  35.104 37.92 38.293 37.944 ;
     RECT  35.104 39.216 38.293 39.24 ;
     RECT  38.293 37.92 38.725 39.24 ;
     RECT  38.725 37.296 38.771 39.24 ;
     RECT  35.104 33.408 38.833 33.432 ;
     RECT  38.833 33.408 39.337 33.576 ;
     RECT  39.337 33.408 39.481 34.2 ;
     RECT  39.481 33.264 39.517 34.2 ;
     RECT  39.049 56.256 40.021 56.28 ;
     RECT  39.517 32.736 40.208 34.2 ;
     RECT  40.069 35.328 40.208 35.352 ;
     RECT  38.771 37.296 40.208 37.944 ;
     RECT  38.771 39.216 40.208 39.24 ;
     RECT  40.021 56.256 40.208 56.376 ;
     RECT  40.208 2.148 40.312 62.652 ;
     RECT  40.312 2.418 40.504 62.382 ;
     RECT  40.504 32.352 40.565 34.632 ;
     RECT  40.504 37.056 40.565 38.184 ;
     RECT  40.565 32.352 40.997 33.576 ;
     RECT  40.504 56.256 41.123 57.576 ;
     RECT  40.504 51.312 41.507 52.008 ;
     RECT  40.504 58.704 41.557 59.256 ;
     RECT  40.997 32.352 41.605 32.376 ;
     RECT  40.997 33.552 41.641 33.576 ;
     RECT  40.565 34.608 41.641 34.632 ;
     RECT  41.641 33.552 41.681 34.632 ;
     RECT  40.565 37.056 41.929 37.08 ;
     RECT  41.929 37.056 41.939 37.128 ;
     RECT  41.557 58.704 42.217 60.216 ;
     RECT  41.557 61.584 42.217 61.608 ;
     RECT  42.217 58.704 42.22 61.608 ;
     RECT  41.123 56.256 42.365 57.288 ;
     RECT  42.365 56.256 42.467 57.144 ;
     RECT  40.504 39.216 42.505 39.24 ;
     RECT  42.397 28.704 42.541 28.728 ;
     RECT  41.605 32.016 42.581 32.376 ;
     RECT  42.541 28.704 42.685 28.968 ;
     RECT  42.685 28.704 42.721 29.016 ;
     RECT  41.641 35.856 42.793 35.88 ;
     RECT  42.22 58.656 42.793 61.608 ;
     RECT  42.721 28.512 42.829 29.016 ;
     RECT  41.929 30.768 42.829 30.792 ;
     RECT  42.793 35.712 42.829 35.88 ;
     RECT  42.829 28.512 42.869 30.792 ;
     RECT  42.793 58.608 42.869 61.608 ;
     RECT  42.893 50.112 42.908 50.136 ;
     RECT  41.681 33.552 42.941 34.2 ;
     RECT  41.507 51.312 42.947 51.336 ;
     RECT  42.505 39.168 42.949 39.24 ;
     RECT  42.829 35.712 42.973 35.976 ;
     RECT  41.939 37.104 42.973 37.128 ;
     RECT  42.869 58.608 42.977 60.12 ;
     RECT  42.908 50.016 42.995 50.136 ;
     RECT  42.869 28.848 43.013 30.792 ;
     RECT  42.421 54.912 43.081 54.936 ;
     RECT  42.941 33.84 43.093 34.2 ;
     RECT  42.829 63.888 43.117 63.912 ;
     RECT  43.117 63.84 43.153 63.912 ;
     RECT  43.013 28.848 43.193 28.968 ;
     RECT  43.153 63.84 43.225 63.96 ;
     RECT  43.225 63.264 43.237 63.96 ;
     RECT  43.093 33.84 43.292 34.44 ;
     RECT  42.973 35.712 43.292 37.128 ;
     RECT  43.292 33.84 43.331 37.128 ;
     RECT  43.253 50.688 43.337 50.712 ;
     RECT  43.081 54.816 43.369 54.936 ;
     RECT  42.757 55.92 43.369 55.944 ;
     RECT  43.193 28.944 43.373 28.968 ;
     RECT  42.949 39.168 43.379 39.624 ;
     RECT  43.379 39.312 43.453 39.624 ;
     RECT  42.467 57.024 43.549 57.144 ;
     RECT  42.869 61.584 43.585 61.608 ;
     RECT  43.237 62.592 43.585 63.96 ;
     RECT  43.331 37.056 43.621 37.128 ;
     RECT  40.565 38.16 43.621 38.184 ;
     RECT  43.453 39.36 43.625 39.624 ;
     RECT  43.013 30.768 43.765 30.792 ;
     RECT  43.369 54.816 43.801 55.944 ;
     RECT  43.549 57.024 43.801 57.192 ;
     RECT  43.621 37.056 43.805 38.184 ;
     RECT  43.331 33.84 43.841 35.736 ;
     RECT  42.977 60 43.861 60.12 ;
     RECT  43.801 54.816 43.873 57.192 ;
     RECT  42.977 58.608 43.873 58.68 ;
     RECT  43.873 54.816 43.877 58.68 ;
     RECT  43.585 61.584 43.907 63.96 ;
     RECT  43.877 58.08 43.957 58.68 ;
     RECT  43.625 39.36 43.985 39.384 ;
     RECT  42.581 32.016 44.125 32.232 ;
     RECT  43.861 60 44.129 60.36 ;
     RECT  43.765 30.768 44.341 30.936 ;
     RECT  43.841 33.84 44.377 34.92 ;
     RECT  43.907 62.16 44.38 63.96 ;
     RECT  43.877 54.816 44.417 56.568 ;
     RECT  44.38 63.888 44.437 63.96 ;
     RECT  43.957 58.08 44.453 58.632 ;
     RECT  44.377 33.36 44.492 34.92 ;
     RECT  44.437 63.888 44.723 64.632 ;
     RECT  44.492 33.312 44.881 34.92 ;
     RECT  44.453 58.08 44.881 58.152 ;
     RECT  44.723 64.512 44.914 64.632 ;
     RECT  44.125 32.016 44.917 32.28 ;
     RECT  44.881 33.312 44.917 35.544 ;
     RECT  44.809 28.704 44.953 28.728 ;
     RECT  44.914 64.512 45.004 64.68 ;
     RECT  45.004 64.656 45.037 64.68 ;
     RECT  44.38 62.16 45.196 62.856 ;
     RECT  45.196 62.16 45.203 62.712 ;
     RECT  44.341 30.336 45.253 30.936 ;
     RECT  44.917 32.016 45.253 35.544 ;
     RECT  44.953 28.704 45.608 28.824 ;
     RECT  45.253 30.336 45.608 35.544 ;
     RECT  43.805 37.056 45.608 37.08 ;
     RECT  44.417 54.816 45.608 55.992 ;
     RECT  44.881 57.84 45.608 58.152 ;
     RECT  44.129 60 45.608 60.12 ;
     RECT  45.203 62.16 45.608 62.652 ;
     RECT  45.608 2.148 45.712 62.652 ;
     RECT  45.712 2.418 45.904 62.382 ;
     RECT  45.904 55.968 46.109 55.992 ;
     RECT  45.904 57.6 46.181 57.864 ;
     RECT  45.904 32.256 46.721 37.032 ;
     RECT  46.721 32.256 46.793 34.632 ;
     RECT  46.181 57.6 46.901 57.624 ;
     RECT  46.721 35.808 47.117 37.032 ;
     RECT  45.904 28.512 47.225 30.936 ;
     RECT  47.225 30.336 47.293 30.936 ;
     RECT  46.793 32.688 47.797 34.632 ;
     RECT  47.797 32.688 47.869 34.776 ;
     RECT  47.117 35.808 47.869 36.84 ;
     RECT  47.293 30.336 48.035 31.368 ;
     RECT  47.869 32.688 48.125 36.84 ;
     RECT  47.225 28.512 48.188 29.208 ;
     RECT  48.188 28.512 48.229 30.168 ;
     RECT  48.125 32.688 48.269 36.648 ;
     RECT  48.269 32.688 48.275 35.352 ;
     RECT  48.275 33.312 48.485 35.352 ;
     RECT  48.229 28.224 49.205 30.168 ;
     RECT  48.269 36.384 49.381 36.648 ;
     RECT  49.381 36.24 49.453 36.648 ;
     RECT  48.485 33.312 49.457 35.016 ;
     RECT  49.453 36.192 49.597 36.648 ;
     RECT  49.597 36.144 49.637 36.648 ;
     RECT  49.457 34.992 49.709 35.016 ;
     RECT  49.637 36.144 49.709 36.408 ;
     RECT  49.205 29.616 49.745 30.168 ;
     RECT  49.709 36.192 49.925 36.408 ;
     RECT  49.925 36.384 49.961 36.408 ;
     RECT  49.745 30.144 49.997 30.168 ;
     RECT  49.205 28.224 50.677 28.248 ;
     RECT  50.677 28.224 51.008 29.064 ;
     RECT  50.849 30.24 51.008 30.264 ;
     RECT  48.035 31.344 51.008 31.368 ;
     RECT  49.457 33.312 51.008 33.672 ;
     RECT  51.008 2.148 51.112 62.652 ;
     RECT  51.112 2.418 51.304 62.382 ;
     RECT  51.304 28.224 51.923 29.496 ;
     RECT  51.304 31.344 51.923 31.368 ;
     RECT  51.923 28.992 52.157 29.496 ;
     RECT  52.157 29.472 52.949 29.496 ;
     RECT  51.304 33.312 56.408 33.672 ;
     RECT  56.408 2.148 56.512 62.652 ;
     RECT  56.512 2.418 56.704 62.382 ;
     RECT  56.704 33.312 61.808 33.672 ;
     RECT  61.808 2.148 61.912 62.652 ;
     RECT  61.912 2.418 62.104 62.382 ;
     RECT  62.104 33.312 67.208 33.672 ;
     RECT  67.208 2.148 67.312 62.652 ;
     RECT  67.312 2.418 67.504 62.382 ;
     RECT  67.504 33.312 72.608 33.672 ;
     RECT  72.608 2.148 72.712 62.652 ;
     RECT  72.712 2.418 72.904 62.382 ;
     RECT  72.904 33.312 78.008 33.672 ;
     RECT  78.008 2.148 78.112 62.652 ;
     RECT  78.112 2.418 78.304 62.382 ;
     RECT  78.304 33.312 79.589 33.672 ;
     RECT  79.589 33.648 80.417 33.672 ;
     RECT  82.645 35.232 83.408 35.256 ;
     RECT  83.269 37.44 83.408 37.464 ;
     RECT  83.269 41.136 83.408 41.16 ;
     RECT  83.408 2.148 83.512 62.652 ;
     RECT  83.512 2.418 83.704 62.382 ;
     RECT  83.704 29.136 84.805 30.984 ;
     RECT  83.704 32.496 84.805 32.616 ;
     RECT  83.704 36.528 84.805 37.32 ;
     RECT  84.805 35.664 84.841 37.512 ;
     RECT  84.805 29.136 84.877 32.904 ;
     RECT  84.841 35.568 84.877 38.088 ;
     RECT  84.877 35.472 85.165 38.088 ;
     RECT  84.877 29.136 85.417 33 ;
     RECT  85.165 35.472 85.453 38.28 ;
     RECT  85.417 29.136 86.281 33.192 ;
     RECT  86.281 29.136 86.364 33.288 ;
     RECT  85.453 35.28 86.364 38.28 ;
    LAYER M5 ;
     RECT  2.4 2.137 2.52 2.151 ;
     RECT  7.8 2.137 7.92 2.151 ;
     RECT  13.2 2.137 13.32 2.151 ;
     RECT  18.6 2.137 18.72 2.151 ;
     RECT  24 2.137 24.12 2.151 ;
     RECT  29.4 2.137 29.52 2.151 ;
     RECT  34.8 2.137 34.92 2.151 ;
     RECT  40.2 2.137 40.32 2.151 ;
     RECT  45.6 2.137 45.72 2.151 ;
     RECT  51 2.137 51.12 2.151 ;
     RECT  56.4 2.137 56.52 2.151 ;
     RECT  61.8 2.137 61.92 2.151 ;
     RECT  67.2 2.137 67.32 2.151 ;
     RECT  72.6 2.137 72.72 2.151 ;
     RECT  78 2.137 78.12 2.151 ;
     RECT  83.4 2.137 83.52 2.151 ;
     RECT  7.8 2.151 8.112 27.061 ;
     RECT  7.68 27.061 8.112 27.109 ;
     RECT  4.464 26.725 5.4 28.117 ;
     RECT  7.056 27.109 8.112 28.117 ;
     RECT  51 2.151 51.312 28.213 ;
     RECT  4.464 28.117 8.112 28.547 ;
     RECT  0.144 28.597 0.168 28.787 ;
     RECT  48.24 28.213 48.264 28.837 ;
     RECT  51 28.213 51.912 29.029 ;
     RECT  5.088 28.547 8.112 29.219 ;
     RECT  5.472 29.219 8.112 29.605 ;
     RECT  5.472 29.605 8.232 29.749 ;
     RECT  45.6 2.151 45.912 30.325 ;
     RECT  4.368 29.749 4.392 30.755 ;
     RECT  45.312 30.325 45.912 30.757 ;
     RECT  47.328 28.837 48.264 30.757 ;
     RECT  45.312 30.757 48.264 30.899 ;
     RECT  10.512 30.901 10.536 31.141 ;
     RECT  45.312 30.899 45.912 31.141 ;
     RECT  5.472 29.749 8.376 31.379 ;
     RECT  48 30.899 48.264 31.379 ;
     RECT  50.88 29.029 51.912 31.379 ;
     RECT  7.008 31.379 8.376 31.619 ;
     RECT  7.68 31.619 8.376 31.955 ;
     RECT  45.264 31.141 45.912 32.243 ;
     RECT  5.472 31.379 5.784 32.485 ;
     RECT  4.512 32.485 5.784 32.723 ;
     RECT  48.24 31.379 48.264 32.723 ;
     RECT  10.272 31.141 10.536 32.725 ;
     RECT  9.696 32.725 10.536 32.965 ;
     RECT  45.504 32.243 45.912 33.013 ;
     RECT  4.512 32.723 5.592 33.251 ;
     RECT  45.504 33.013 46.776 33.301 ;
     RECT  7.68 31.955 8.328 33.541 ;
     RECT  44.544 33.301 46.776 33.683 ;
     RECT  44.544 33.683 46.152 33.731 ;
     RECT  4.56 33.251 5.496 33.779 ;
     RECT  9.648 32.965 10.536 33.781 ;
     RECT  44.544 33.731 44.568 33.829 ;
     RECT  6.816 33.541 8.328 33.877 ;
     RECT  9.648 33.781 10.728 33.877 ;
     RECT  6.816 33.877 10.728 34.165 ;
     RECT  40.2 2.151 40.512 34.165 ;
     RECT  43.776 33.829 44.568 34.405 ;
     RECT  4.56 33.779 4.584 34.741 ;
     RECT  4.416 34.741 4.584 34.787 ;
     RECT  6.816 34.165 10.824 34.787 ;
     RECT  43.104 34.405 44.568 34.931 ;
     RECT  49.008 33.301 49.032 35.027 ;
     RECT  7.104 34.787 10.824 35.123 ;
     RECT  45.6 33.731 46.152 35.171 ;
     RECT  43.104 34.931 43.8 35.315 ;
     RECT  10.8 35.123 10.824 35.363 ;
     RECT  40.08 34.165 40.512 35.363 ;
     RECT  7.104 35.123 9.72 35.939 ;
     RECT  7.104 35.939 9.144 36.227 ;
     RECT  7.104 36.227 8.112 37.091 ;
     RECT  41.904 35.845 41.928 37.091 ;
     RECT  83.4 2.151 83.712 37.429 ;
     RECT  9.12 36.227 9.144 37.955 ;
     RECT  43.104 35.315 43.368 38.149 ;
     RECT  4.416 34.787 4.44 38.387 ;
     RECT  0.192 32.581 0.216 38.629 ;
     RECT  0.192 38.629 0.312 38.819 ;
     RECT  38.736 37.285 38.76 38.819 ;
     RECT  42.96 38.149 43.704 39.395 ;
     RECT  83.28 37.429 83.712 41.171 ;
     RECT  28.08 37.909 28.104 42.803 ;
     RECT  0.192 38.819 0.216 43.091 ;
     RECT  42.96 39.395 43.416 50.101 ;
     RECT  42.912 50.101 43.416 51.347 ;
     RECT  40.2 35.363 40.512 51.973 ;
     RECT  40.2 51.973 41.496 54.901 ;
     RECT  43.296 51.347 43.416 54.901 ;
     RECT  40.2 54.901 43.416 54.947 ;
     RECT  45.6 35.171 45.912 55.237 ;
     RECT  40.2 54.947 42.456 57.059 ;
     RECT  44.976 55.237 45.912 57.875 ;
     RECT  42.432 57.059 42.456 58.645 ;
     RECT  42.24 58.645 42.456 59.125 ;
     RECT  42.24 59.125 42.744 59.171 ;
     RECT  40.2 57.059 41.112 59.221 ;
     RECT  40.2 59.221 41.592 59.267 ;
     RECT  43.92 58.645 43.944 60.035 ;
     RECT  42.72 59.171 42.744 60.131 ;
     RECT  41.568 59.267 41.592 61.619 ;
     RECT  43.872 60.085 43.896 62.149 ;
     RECT  43.872 62.149 44.52 62.197 ;
     RECT  43.872 62.197 44.616 62.293 ;
     RECT  45.6 57.875 45.912 62.293 ;
     RECT  43.728 62.293 45.912 62.581 ;
     RECT  2.4 2.151 2.712 62.649 ;
     RECT  7.8 37.091 8.112 62.649 ;
     RECT  13.2 2.151 13.512 62.649 ;
     RECT  18.6 2.151 18.912 62.649 ;
     RECT  24 2.151 24.312 62.649 ;
     RECT  29.4 2.151 29.712 62.649 ;
     RECT  34.8 2.151 35.112 62.649 ;
     RECT  40.2 59.267 40.512 62.649 ;
     RECT  43.248 62.581 45.912 62.649 ;
     RECT  51 31.379 51.312 62.649 ;
     RECT  56.4 2.151 56.712 62.649 ;
     RECT  61.8 2.151 62.112 62.649 ;
     RECT  67.2 2.151 67.512 62.649 ;
     RECT  72.6 2.151 72.912 62.649 ;
     RECT  78 2.151 78.312 62.649 ;
     RECT  83.4 41.171 83.712 62.649 ;
     RECT  2.4 62.649 2.52 62.663 ;
     RECT  7.8 62.649 7.92 62.663 ;
     RECT  13.2 62.649 13.32 62.663 ;
     RECT  18.6 62.649 18.72 62.663 ;
     RECT  24 62.649 24.12 62.663 ;
     RECT  29.4 62.649 29.52 62.663 ;
     RECT  34.8 62.649 34.92 62.663 ;
     RECT  40.2 62.649 40.32 62.663 ;
     RECT  43.248 62.649 45.72 62.663 ;
     RECT  51 62.649 51.12 62.663 ;
     RECT  56.4 62.649 56.52 62.663 ;
     RECT  61.8 62.649 61.92 62.663 ;
     RECT  67.2 62.649 67.32 62.663 ;
     RECT  72.6 62.649 72.72 62.663 ;
     RECT  78 62.649 78.12 62.663 ;
     RECT  83.4 62.649 83.52 62.663 ;
     RECT  43.248 62.663 45.192 64.784 ;
     RECT  4.464 28.547 5.088 29.219 ;
     RECT  45.912 28.837 47.328 30.757 ;
     RECT  4.464 29.219 5.472 29.749 ;
     RECT  4.392 29.749 5.472 30.755 ;
     RECT  5.784 31.379 7.008 31.619 ;
     RECT  8.328 31.955 8.376 32.725 ;
     RECT  45.264 32.243 45.504 33.301 ;
     RECT  5.592 32.723 5.784 33.251 ;
     RECT  8.328 32.725 9.696 32.965 ;
     RECT  8.328 32.965 9.648 33.877 ;
     RECT  4.512 33.251 4.56 34.741 ;
     RECT  5.496 33.251 5.784 33.541 ;
     RECT  5.496 33.541 6.816 33.779 ;
     RECT  44.568 33.731 45.6 34.931 ;
     RECT  9.72 35.123 10.8 35.363 ;
     RECT  40.512 35.845 41.904 37.091 ;
     RECT  41.928 35.845 43.104 37.091 ;
     RECT  8.112 36.227 9.12 37.955 ;
     RECT  42.96 37.091 43.104 38.149 ;
     RECT  38.76 37.285 40.2 38.819 ;
     RECT  28.104 37.909 29.4 42.803 ;
     RECT  41.112 57.059 42.432 58.645 ;
     RECT  41.112 58.645 42.24 59.171 ;
     RECT  42.456 58.645 43.92 59.125 ;
     RECT  42.744 59.125 43.92 60.035 ;
     RECT  41.112 59.171 42.72 59.221 ;
     RECT  41.592 59.221 42.72 60.131 ;
     RECT  40.512 59.267 41.568 61.619 ;
     RECT  42.744 60.035 43.896 60.085 ;
     RECT  42.744 60.085 43.872 60.131 ;
     RECT  44.52 62.149 45.6 62.197 ;
     RECT  44.616 62.197 45.6 62.293 ;
  END
END ot_hgi_sm_pub_cmd
END LIBRARY
